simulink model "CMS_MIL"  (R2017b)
settings: Solver=FixedStepDiscrete  StartTime=0.0  StopTime=10.0  FixedStep=0.01  RelTol=1e-3  EnableMultiTasking=on
undefined symbols (not defined in the file): ASWTYPE_FALSE, ASWTYPE_TRUE, CcCMS_CANSendDelay_ms, CcCMS_ChrgMaxPackVoltLimt_V, CcCMS_ChrgRemTimeDftValDelayTime_ms, CcCMS_GBChgModeStayInCloseStatus_ms, CcCMS_PeakVoltCh_V, CcCMS_PeakVoltDisCh_V, CcSOC_DispSOCHighThrhd_pct, CMS09D_RUNTIME_MS, CMS_CONST0_NUMB, CMS_CONST1000_NUMB, CMS_CONST100_NUMB, CMS_CONST1_NUMB, CMS_CONST2047_NUMB, CMS_CONST2_NUMB, CMS_CONST3_NUMB, CMS_CONST4_NUMB, CMS_CONST5_NUMB, CMS_CONST6_NUMB, CMS_CONST7_NUMB, CMS_CONSTF1_NUMB, Enum_ACCACChrgState, Enum_CMSACChgMode, Enum_CMSBmsSelfChk, Enum_CMSBmsSt, Enum_CMSChgMode, Enum_CMSDCChgMode, Enum_CMSHVBatFltSevrtyStat, Enum_CMSHVConnSt, Enum_CMSPreThmMode, Enum_CMSPreThmReq, Enum_CTCCtrCtlConnMode, Enum_CTCCtrCtlState, Enum_DCCDCChrgState, Enum_DCCDCConnSt, Enum_ISOHVIsoFltLevel, Enum_LDPChrgGunState, Enum_MSMBMUState, Enum_ODPCCState, Enum_UDSAreaSel, Enum_VDPPreThmEna
libraries: AIWAYS_Powertrain_BMS_lib x156
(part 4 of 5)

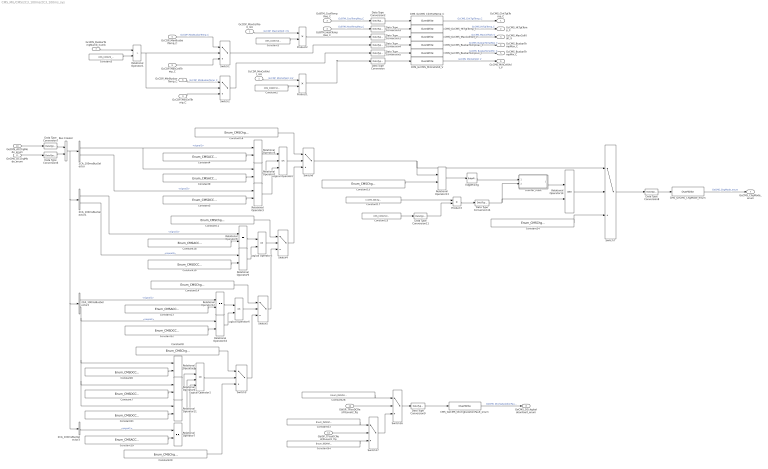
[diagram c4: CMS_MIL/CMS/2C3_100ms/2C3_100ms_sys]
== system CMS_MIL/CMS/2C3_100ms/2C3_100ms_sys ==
  GcCDP_MinCellVolt_mV : Inport
  GcCDP_MaxCellVolt_mV : Inport  Port=2
  GcBTM_CoolTempReq_C : Inport  Port=3
  GcBTM_HeatTempReq_C : Inport  Port=4
  GcCDP_MaxBusbarTemp_C : Inport  Port=5
  GcCDP_MinBusbarTemp_C : Inport  Port=6
  GcUDS_BusbarTempNumb_numb : Inport  Port=7
  GcCDP_MaxCellTemp_C : Inport  Port=8
  GcCDP_MinCellTemp_C : Inport  Port=9
  GeCMS_ACChgMode_enum : Inport  Port=10
  GeCMS_DCChgMode_enum : Inport  Port=11
  GbISP_TFIsoDCResFltLevel2_flg : Inport  Port=12
  GbISP_TFIsoDCResFltLevel1_flg : Inport  Port=13
  2CA_100msBusSelector : BusSelector  OutputSignals=signal1,signal2
  2CA_100msBusSelector1 : BusSelector  OutputSignals=signal1,signal2
  2CA_100msBusSelector2 : BusSelector  OutputSignals=signal1,signal2
  2CA_100msBusSelector3 : BusSelector  OutputSignals=signal1
  Bus Creator : BusCreator  Inputs=2
  CMS_GcCMS_BusbarTempMax_C : AIWAYS_Powertrain_BMS_lib/Signals/OverWrite  OverWrite_Value=CcCMS_BusbarTempMaxOvr_C  OverWrite_flag=CbCMS_BusbarTempMaxOvrSwt_flg
  CMS_GcCMS_BusbarTempMin_C : AIWAYS_Powertrain_BMS_lib/Signals/OverWrite  OverWrite_Value=CcCMS_BusbarTempMinOvr_C  OverWrite_flag=CbCMS_BusbarTempMinOvrSwt_flg
  CMS_GcCMS_ClntTgtTemp_C : AIWAYS_Powertrain_BMS_lib/Signals/OverWrite  OverWrite_Value=CcCMS_ClntTgtTempOvr_C  OverWrite_flag=CbCMS_ClntTgtTempOvrSwt_flg
  CMS_GcCMS_HtTgtTemp_C : AIWAYS_Powertrain_BMS_lib/Signals/OverWrite  OverWrite_Value=CcCMS_HtTgtTempOvr_C  OverWrite_flag=CbCMS_HtTgtTempOvrSwt_flg
  CMS_GcCMS_MaxCellVolt_V : AIWAYS_Powertrain_BMS_lib/Signals/OverWrite  OverWrite_Value=CcCMS_MaxCellVoltOvr_V  OverWrite_flag=CbCMS_MaxCellVoltOvrSwt_flg
  CMS_GcCMS_MinCellVolt_V : AIWAYS_Powertrain_BMS_lib/Signals/OverWrite  OverWrite_Value=CcCMS_MinCellVoltOvr_V  OverWrite_flag=CbCMS_MinCellVoltOvrSwt_flg
  CMS_GeCMS_ChgMode_enum : AIWAYS_Powertrain_BMS_lib/Signals/OverWrite  OverWrite_Value=CeCMS_ChgModeOvr_enum  OverWrite_flag=CbCMS_ChgModeOvrSwt_flg
  CMS_GeCMS_DCchgIsolationFault_enum : AIWAYS_Powertrain_BMS_lib/Signals/OverWrite  OverWrite_Value=CeCMS_DCchgIsolationFaultOvr_enum  OverWrite_flag=CbCMS_DCchgIsolationFaultOvrSwt_flg
  Constant1 : Constant  Value=CMS_CONST1000_NUMB
  Constant10 : Constant  Value=Enum_CMSDCChgMode.Enum_CMSDCChgMode_ChgEnd
  Constant11 : Constant  Value=Enum_CMSChgMode.Enum_CMSChgMode_Closed
  Constant12 : Constant  Value=Enum_CMSDCChgMode.Enum_CMSDCChgMode_ChgFault
  Constant13 : Constant  Value=Enum_CMSACChgMode.Enum_CMSACChgMode_ChrgFault
  Constant14 : Constant  Value=Enum_CMSChgMode.Enum_CMSChgMode_Abnormal
  Constant15 : Constant  Value=Enum_CMSChgMode.Enum_CMSChgMode_Closed
  Constant16 : Constant  Value=Enum_CMSChgMode.Enum_CMSChgMode_ParkingCharging
  Constant17 : Constant  Value=CcCMS_GBChgModeStayInCloseStatus_ms
  Constant18 : Constant  Value=Enum_CMSACChgMode.Enum_CMSACChgMode_ChrgEnd
  Constant19 : Constant  Value=Enum_CMSACChgMode.Enum_CMSACChgMode_Default
  Constant2 : Constant  Value=CMS_CONST1000_NUMB
  Constant20 : Constant  Value=Enum_CMSChgMode.Enum_CMSChgMode_Invalid
  Constant21 : Constant  Value=Enum_CMSDCChgMode.Enum_CMSDCChgMode_Default
  Constant23 : Constant  Value=CMS_CONST100_NUMB
  Constant24 : Constant  Value=Enum_CMSChgMode.Enum_CMSChgMode_Closed
  Constant28 : Constant  Value=Enum_ISOHVIsoFltLevel.Enum_ISOHVIsoFltLevel_FltLevel3
  Constant3 : Constant  Value=CMS_CONST0_NUMB
  Constant4 : Constant  Value=Enum_CMSACChgMode.Enum_CMSACChgMode_PreHeat
  Constant5 : Constant  Value=Enum_CMSDCChgMode.Enum_CMSDCChgMode_Chging
  Constant53 : Constant  Value=Enum_ISOHVIsoFltLevel.Enum_ISOHVIsoFltLevel_FltLevel2
  Constant54 : Constant  Value=Enum_ISOHVIsoFltLevel.Enum_ISOHVIsoFltLevel_Default
  Constant6 : Constant  Value=Enum_CMSDCChgMode.Enum_CMSDCChgMode_HandOver
  Constant7 : Constant  Value=Enum_CMSDCChgMode.Enum_CMSDCChgMode_ParaConfig
  Constant8 : Constant  Value=Enum_CMSChgMode.Enum_CMSChgMode_Uncharged
  Constant9 : Constant  Value=Enum_CMSACChgMode.Enum_CMSACChgMode_Chrging
  Data Type Conversion{,1,4..5} (4 alike) : DataTypeConversion  RndMeth=Round
  Data Type Conversion{2..3,6..9,11} (7 alike) : DataTypeConversion
  Data Type Conversion14 : DataTypeConversion  OutDataTypeStr=uint16
  EdgeRising : AIWAYS_Powertrain_BMS_lib/Logical Operators/EdgeRising
  Logical Operator1 : Logic  Operator=OR  Inputs=4  AllPortsSameDT=off  OutDataTypeStr=boolean
  Logical Operator2 : Logic  Operator=OR  Inputs=3  AllPortsSameDT=off  OutDataTypeStr=boolean
  Logical Operator3 : Logic  Operator=OR  AllPortsSameDT=off  OutDataTypeStr=boolean
  Logical Operator4 : Logic  Operator=OR  AllPortsSameDT=off  OutDataTypeStr=boolean
  Product1 : Product  Inputs=*/  OutDataTypeStr=single
  Product2 : Product  Inputs=*/  OutDataTypeStr=single
  Product3 : Product  Inputs=*/  OutDataTypeStr=Inherit: Inherit via back propagation
  Relational Operator1 : RelationalOperator  Operator=>  OutDataTypeStr=boolean
  Relational Operator{2..13} (12 alike) : RelationalOperator  Operator===  OutDataTypeStr=boolean
  Relational Operator14 : RelationalOperator  OutDataTypeStr=boolean
  Switch1 : Switch  Criteria=u2 ~= 0  Threshold=1  RndMeth=Zero
  Switch{3..7,16..17} (7 alike) : Switch  Criteria=u2 ~= 0
  Switch2 : Switch  Criteria=u2 ~= 0  Threshold=1  RndMeth=Zero
  counter_reset : Subsystem
  GcCMS_ClntTgtTemp_C : Outport
  GcCMS_HtTgtTemp_C : Outport  Port=2
  GcCMS_MaxCellVolt_V : Outport  Port=3
  GcCMS_BusbarTempMax_C : Outport  Port=4
  GcCMS_BusbarTempMin_C : Outport  Port=5
  GcCMS_MinCellVolt_V : Outport  Port=6
  GeCMS_ChgMode_enum : Outport  Port=7
  GeCMS_DCchgIsolationFault_enum : Outport  Port=8
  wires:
  CMS_GcCMS_ClntTgtTemp_C/1 -> GcCMS_ClntTgtTemp_C/1  "GcCMS_ClntTgtTemp_C"
  CMS_GcCMS_BusbarTempMin_C/1 -> GcCMS_BusbarTempMin_C/1  "GcCMS_BusbarTempMin_C"
  CMS_GcCMS_BusbarTempMax_C/1 -> GcCMS_BusbarTempMax_C/1  "GcCMS_BusbarTempMax_C"
  CMS_GcCMS_MaxCellVolt_V/1 -> GcCMS_MaxCellVolt_V/1  "GcCMS_MaxCellVolt_V"
  CMS_GcCMS_HtTgtTemp_C/1 -> GcCMS_HtTgtTemp_C/1  "GcCMS_HtTgtTemp_C"
  Constant2/1 -> Product1/2
  GcCDP_MinCellVolt_mV/1 -> Product1/1  "GcCDP_MinCellVolt_mV"
  CMS_GcCMS_MinCellVolt_V/1 -> GcCMS_MinCellVolt_V/1  "GcCMS_MinCellVolt_V"
  Product1/1 -> Data Type Conversion/1
  GcBTM_CoolTempReq_C/1 -> Data Type Conversion2/1  "GcBTM_CoolTempReq_C"
  GcBTM_HeatTempReq_C/1 -> Data Type Conversion3/1  "GcBTM_HeatTempReq_C"
  GcCDP_MaxBusbarTemp_C/1 -> Switch1/1  "GcCDP_MaxBusbarTemp_C"
  GcCDP_MinBusbarTemp_C/1 -> Switch2/1  "GcCDP_MinBusbarTemp_C"
  Data Type Conversion/1 -> CMS_GcCMS_MinCellVolt_V/1
  GcCDP_MaxCellVolt_mV/1 -> Product2/1  "GcCDP_MaxCellVolt_mV"
  Product2/1 -> Data Type Conversion1/1
  Constant1/1 -> Product2/2
  Data Type Conversion1/1 -> CMS_GcCMS_MaxCellVolt_V/1
  Data Type Conversion2/1 -> CMS_GcCMS_ClntTgtTemp_C/1
  Data Type Conversion3/1 -> CMS_GcCMS_HtTgtTemp_C/1
  Data Type Conversion4/1 -> CMS_GcCMS_BusbarTempMax_C/1
  Data Type Conversion5/1 -> CMS_GcCMS_BusbarTempMin_C/1
  GcUDS_BusbarTempNumb_numb/1 -> Relational Operator1/1
  Constant3/1 -> Relational Operator1/2
  Relational Operator1/1 -> Switch2/2, Switch1/2
  GcCDP_MaxCellTemp_C/1 -> Switch1/3
  Switch1/1 -> Data Type Conversion4/1
  GcCDP_MinCellTemp_C/1 -> Switch2/3
  Switch2/1 -> Data Type Conversion5/1
  Switch3/1 -> Switch5/3
  Relational Operator7/1 -> Logical Operator1/4
  Relational Operator10/1 -> Logical Operator4/2
  Logical Operator3/1 -> Switch4/2
  GeCMS_ACChgMode_enum/1 -> Data Type Conversion7/1
  Constant16/1 -> Switch6/1
  Data Type Conversion8/1 -> CMS_GeCMS_ChgMode_enum/1
  Constant4/1 -> Relational Operator5/2
  Constant9/1 -> Relational Operator2/2
  Constant21/1 -> Relational Operator11/2
  Constant18/1 -> Relational Operator8/2
  2CA_100msBusSelector2/1 -> Relational Operator12/1  "<signal1>"
  Relational Operator3/1 -> Logical Operator2/3
  Constant10/1 -> Relational Operator9/2
  Relational Operator2/1 -> Logical Operator2/2
  Constant20/1 -> Switch3/3
  2CA_100msBusSelector/1 -> Relational Operator5/1, Relational Operator2/1  "<signal1>"
  Logical Operator1/1 -> Switch3/2
  Constant5/1 -> Relational Operator3/2
  Constant8/1 -> Switch3/1
  Relational Operator11/1 -> Logical Operator1/3
  Constant14/1 -> Switch5/1
  Constant6/1 -> Relational Operator4/2
  Switch4/1 -> Switch6/3
  2CA_100msBusSelector1/1 -> Relational Operator8/1  "<signal1>"
  Constant13/1 -> Relational Operator12/2
  Switch5/1 -> Switch4/3
  Relational Operator6/1 -> Logical Operator1/2
  Constant12/1 -> Relational Operator10/2
  Logical Operator2/1 -> Switch6/2
  2CA_100msBusSelector3/1 -> Relational Operator7/1  "<signal1>"
  Relational Operator9/1 -> Logical Operator3/2
  Data Type Conversion7/1 -> Bus Creator/1
  2CA_100msBusSelector/2 -> Relational Operator3/1  "<signal2>"
  Constant7/1 -> Relational Operator6/2
  2CA_100msBusSelector1/2 -> Relational Operator9/1  "<signal2>"
  GeCMS_DCChgMode_enum/1 -> Data Type Conversion6/1
  Bus Creator/1 -> 2CA_100msBusSelector/1, 2CA_100msBusSelector1/1, 2CA_100msBusSelector2/1, 2CA_100msBusSelector3/1
  Relational Operator12/1 -> Logical Operator4/1
  2CA_100msBusSelector2/2 -> Relational Operator10/1, Relational Operator6/1, Relational Operator11/1, Relational Operator4/1  "<signal2>"
  Data Type Conversion6/1 -> Bus Creator/2
  Relational Operator8/1 -> Logical Operator3/1
  Relational Operator5/1 -> Logical Operator2/1
  CMS_GeCMS_ChgMode_enum/1 -> GeCMS_ChgMode_enum/1  "GeCMS_ChgMode_enum"
  Logical Operator4/1 -> Switch5/2
  Switch6/1 -> Relational Operator13/1, Switch7/1
  Constant19/1 -> Relational Operator7/2
  Relational Operator4/1 -> Logical Operator1/1
  Constant11/1 -> Switch4/1
  Switch17/1 -> Switch16/3
  Constant54/1 -> Switch17/3
  GbISP_TFIsoDCResFltLevel2_flg/1 -> Switch16/2
  GbISP_TFIsoDCResFltLevel1_flg/1 -> Switch17/2
  Constant28/1 -> Switch16/1
  Constant53/1 -> Switch17/1
  Switch16/1 -> Data Type Conversion9/1
  CMS_GeCMS_DCchgIsolationFault_enum/1 -> GeCMS_DCchgIsolationFault_enum/1  "GeCMS_DCchgIsolationFault_enum"
  Data Type Conversion9/1 -> CMS_GeCMS_DCchgIsolationFault_enum/1
  Constant15/1 -> Relational Operator13/2
  Relational Operator13/1 -> EdgeRising/1
  Relational Operator14/1 -> Switch7/2
  Switch7/1 -> Data Type Conversion8/1
  Constant23/1 -> Data Type Conversion11/1
  Data Type Conversion11/1 -> Product3/2
  counter_reset/1(cnt_num) -> Relational Operator14/1
  Data Type Conversion14/1 -> Relational Operator14/2, counter_reset/2(max_cnt)
  Constant24/1 -> Switch7/3
  EdgeRising/1 -> counter_reset/1(reset)
  Product3/1 -> Data Type Conversion14/1
  Constant17/1 -> Product3/1

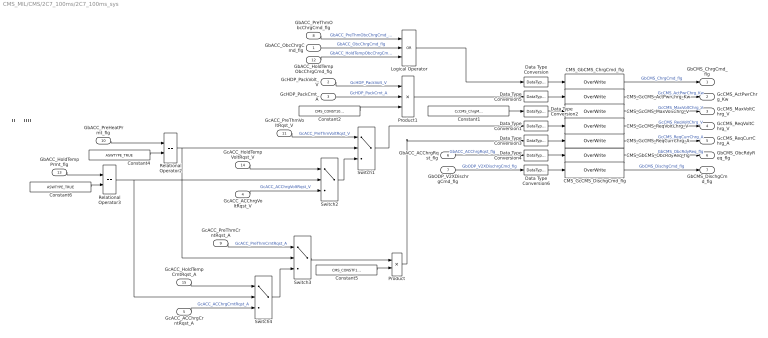
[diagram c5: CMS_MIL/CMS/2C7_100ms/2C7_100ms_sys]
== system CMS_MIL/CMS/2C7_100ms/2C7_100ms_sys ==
  note: 预加热 保温 充电
  GbACC_ObcChrgCmd_flg : Inport
  GcHDP_PackVolt_V : Inport  Port=2
  GcHDP_PackCrnt_A : Inport  Port=3
  GcACC_ACChrgVoltRqst_V : Inport  Port=4
  GcACC_ACChrgCrntRqst_A : Inport  Port=5
  GbACC_ACChrgRqst_flg : Inport  Port=6
  GbODP_V2XDischrgCmd_flg : Inport  Port=7
  GbACC_PreThmObcChrgCmd_flg : Inport  Port=8
  GcACC_PreThmCrntRqst_A : Inport  Port=9
  GbACC_PreHeatPrmt_flg : Inport  Port=10
  GcACC_PreThmVoltRqst_V : Inport  Port=11
  GbACC_HoldTempObcChrgCmd_flg : Inport  Port=12
  GbACC_HoldTempPrmt_flg : Inport  Port=13
  GcACC_HoldTempVoltRqst_V : Inport  Port=14
  GcACC_HoldTempCrntRqst_A : Inport  Port=15
  CMS_GbCMS_ChrgCmd_flg : AIWAYS_Powertrain_BMS_lib/Signals/OverWrite  OverWrite_Value=CbCMS_ChrgCmdOvr_flg  OverWrite_flag=CbCMS_ChrgCmdOvrSwt_flg
  CMS_GbCMS_ObcRdyReq_flg : AIWAYS_Powertrain_BMS_lib/Signals/OverWrite  OverWrite_Value=CbCMS_ObcRdyReqOvr_flg  OverWrite_flag=CbCMS_ObcRdyReqOvrSwt_flg
  CMS_GcCMS_ActPwrChrg_Kw : AIWAYS_Powertrain_BMS_lib/Signals/OverWrite  OverWrite_Value=CcCMS_ActPwrChrgOvr_Kw  OverWrite_flag=CbCMS_ActPwrChrgOvrSwt_flg
  CMS_GcCMS_DischgCmd_flg : AIWAYS_Powertrain_BMS_lib/Signals/OverWrite  OverWrite_Value=CbCMS_DischgCmdOvr_flg  OverWrite_flag=CbCMS_DischgCmdOvrSwt_flg
  CMS_GcCMS_MaxVoltChrg_V : AIWAYS_Powertrain_BMS_lib/Signals/OverWrite  OverWrite_Value=CcCMS_MaxVoltChrgOvr_V  OverWrite_flag=CbCMS_MaxVoltChrgOvrSwt_flg
  CMS_GcCMS_ReqCurrChrg_A : AIWAYS_Powertrain_BMS_lib/Signals/OverWrite  OverWrite_Value=CcCMS_ReqCurrChrgOvr_A  OverWrite_flag=CbCMS_ReqCurrChrgOvrSwt_flg
  CMS_GcCMS_ReqVoltChrg_V : AIWAYS_Powertrain_BMS_lib/Signals/OverWrite  OverWrite_Value=CcCMS_ReqVoltChrgOvr_V  OverWrite_flag=CbCMS_ReqVoltChrgOvrSwt_flg
  Constant1 : Constant  Value=CcCMS_ChrgMaxPackVoltLimt_V
  Constant2 : Constant  Value=CMS_CONST1000_NUMB
  Constant4 : Constant  Value=ASWTYPE_TRUE
  Constant5 : Constant  Value=CMS_CONSTF1_NUMB
  Constant6 : Constant  Value=ASWTYPE_TRUE
  Data Type Conversion{,1..6} (7 alike) : DataTypeConversion
  Logical Operator : Logic  Operator=OR  Inputs=3  AllPortsSameDT=off  OutDataTypeStr=boolean
  Product : Product  OutDataTypeStr=Inherit: Inherit via back propagation
  Product1 : Product  Inputs=**/  OutDataTypeStr=single
  Relational Operator2 : RelationalOperator  Operator===  OutDataTypeStr=boolean
  Relational Operator3 : RelationalOperator  Operator===  OutDataTypeStr=boolean
  Switch{1..4} (4 alike) : Switch  Criteria=u2 ~= 0  Threshold=1  RndMeth=Zero
  GbCMS_ChrgCmd_flg : Outport
  GcCMS_ActPwrChrg_Kw : Outport  Port=2
  GcCMS_MaxVoltChrg_V : Outport  Port=3
  GcCMS_ReqVoltChrg_V : Outport  Port=4
  GcCMS_ReqCurrChrg_A : Outport  Port=5
  GbCMS_ObcRdyReq_flg : Outport  Port=6
  GbCMS_DischgCmd_flg : Outport  Port=7
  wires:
  CMS_GbCMS_ChrgCmd_flg/1 -> GbCMS_ChrgCmd_flg/1  "GbCMS_ChrgCmd_flg"
  CMS_GcCMS_ActPwrChrg_Kw/1 -> GcCMS_ActPwrChrg_Kw/1  "GcCMS_ActPwrChrg_Kw"
  CMS_GcCMS_MaxVoltChrg_V/1 -> GcCMS_MaxVoltChrg_V/1  "GcCMS_MaxVoltChrg_V"
  CMS_GcCMS_ReqVoltChrg_V/1 -> GcCMS_ReqVoltChrg_V/1  "GcCMS_ReqVoltChrg_V"
  CMS_GcCMS_ReqCurrChrg_A/1 -> GcCMS_ReqCurrChrg_A/1  "GcCMS_ReqCurrChrg_A"
  CMS_GbCMS_ObcRdyReq_flg/1 -> GbCMS_ObcRdyReq_flg/1  "GbCMS_ObcRdyReq_flg"
  CMS_GcCMS_DischgCmd_flg/1 -> GbCMS_DischgCmd_flg/1  "GbCMS_DischgCmd_flg"
  GbACC_ObcChrgCmd_flg/1 -> Logical Operator/2  "GbACC_ObcChrgCmd_flg"
  Data Type Conversion/1 -> CMS_GbCMS_ChrgCmd_flg/1
  GcHDP_PackVolt_V/1 -> Product1/1  "GcHDP_PackVolt_V"
  GcHDP_PackCrnt_A/1 -> Product1/2  "GcHDP_PackCrnt_A"
  Product1/1 -> Data Type Conversion5/1
  Constant2/1 -> Product1/3
  GcACC_ACChrgVoltRqst_V/1 -> Switch2/3  "GcACC_ACChrgVoltRqst_V"
  GcACC_ACChrgCrntRqst_A/1 -> Switch4/3  "GcACC_ACChrgCrntRqst_A"
  GbACC_ACChrgRqst_flg/1 -> Data Type Conversion4/1  "GbACC_ACChrgRqst_flg"
  Data Type Conversion6/1 -> CMS_GcCMS_DischgCmd_flg/1
  Data Type Conversion1/1 -> CMS_GcCMS_ReqVoltChrg_V/1
  Data Type Conversion2/1 -> CMS_GcCMS_MaxVoltChrg_V/1
  Data Type Conversion3/1 -> CMS_GcCMS_ReqCurrChrg_A/1
  Data Type Conversion4/1 -> CMS_GbCMS_ObcRdyReq_flg/1
  Data Type Conversion5/1 -> CMS_GcCMS_ActPwrChrg_Kw/1
  GbODP_V2XDischrgCmd_flg/1 -> Data Type Conversion6/1  "GbODP_V2XDischrgCmd_flg"
  Constant1/1 -> Data Type Conversion2/1
  GbACC_PreThmObcChrgCmd_flg/1 -> Logical Operator/1  "GbACC_PreThmObcChrgCmd_flg"
  Logical Operator/1 -> Data Type Conversion/1
  Relational Operator2/1 -> Switch1/2, Switch3/2
  GcACC_PreThmCrntRqst_A/1 -> Switch3/1  "GcACC_PreThmCrntRqst_A"
  Switch3/1 -> Product/1
  GbACC_PreHeatPrmt_flg/1 -> Relational Operator2/1
  Constant4/1 -> Relational Operator2/2
  GcACC_PreThmVoltRqst_V/1 -> Switch1/1  "GcACC_PreThmVoltRqst_V"
  Switch1/1 -> Data Type Conversion1/1
  Constant5/1 -> Product/2
  Product/1 -> Data Type Conversion3/1
  GbACC_HoldTempObcChrgCmd_flg/1 -> Logical Operator/3  "GbACC_HoldTempObcChrgCmd_flg"
  Constant6/1 -> Relational Operator3/2
  GbACC_HoldTempPrmt_flg/1 -> Relational Operator3/1
  Relational Operator3/1 -> Switch4/2, Switch2/2
  Switch2/1 -> Switch1/3
  GcACC_HoldTempVoltRqst_V/1 -> Switch2/1
  Switch4/1 -> Switch3/3
  GcACC_HoldTempCrntRqst_A/1 -> Switch4/1

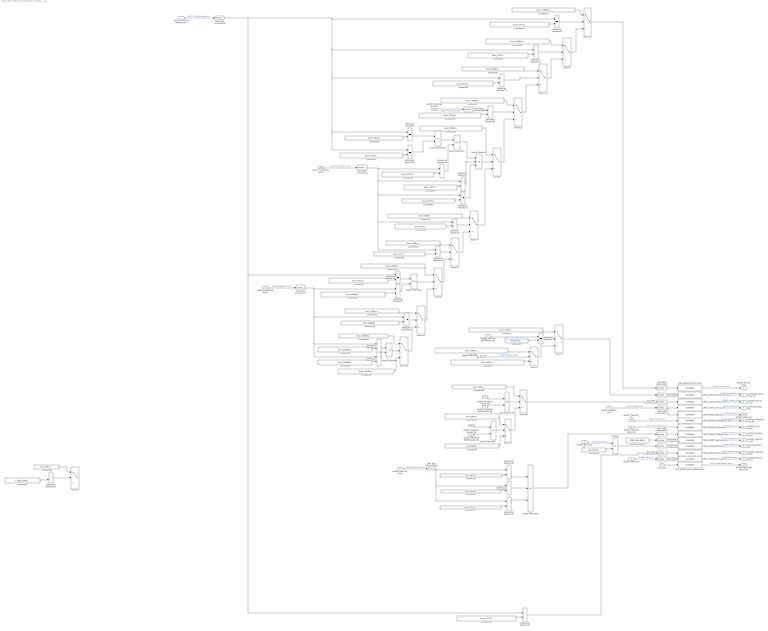
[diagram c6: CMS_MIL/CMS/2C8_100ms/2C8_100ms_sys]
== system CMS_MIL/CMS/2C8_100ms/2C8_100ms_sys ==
  GeCTC_CtrCtlConnMode_enum : Inport
  GbMSM_SelfCheck_flg : Inport  Port=2
  GcSOC_DispSOC_pct : Inport  Port=3
  GbISP_TFHvilLFlt_flg : Inport  Port=4
  GeFTC_FltLvlOnCAN_enum : Inport  Port=5
  GcSOH_PackSOH_pct : Inport  Port=6
  GcHDP_HallCrnt_A : Inport  Port=7
  GbMSM_SelfChckMaxTiReach_flg : Inport  Port=8
  GeMSM_BMUState_enum : Inport  Port=9
  GeCTC_CtrCtlState_enum : Inport  Port=10
  GeODP_ObcCcSt_enum : Inport  Port=11
  GeVDP_PreThmEna_enum : Inport  Port=12
  GbISP_TFIsoResFltLevel2_flg : Inport  Port=13
  GbISP_TFIsoHVoffResFltLevel2_flg : Inport  Port=14
  GbISP_TFIsoResFltLevel1_flg : Inport  Port=15
  GbISP_TFIsoHVoffResFltLevel1_flg : Inport  Port=16
  CMS_GbCMS_HvilOpenFault_flg : AIWAYS_Powertrain_BMS_lib/Signals/OverWrite  OverWrite_Value=CbCMS_HvilOpenFaultOvr_flg  OverWrite_flag=CbCMS_HvilOpenFaultOvrSwt_flg
  CMS_GcCMS_BattSoh_pct : AIWAYS_Powertrain_BMS_lib/Signals/OverWrite  OverWrite_Value=CcCMS_BattSohOvr_pct  OverWrite_flag=CbCMS_BattSohOvrSwt_flg
  CMS_GcCMS_ChgSOCset_pct : AIWAYS_Powertrain_BMS_lib/Signals/OverWrite  OverWrite_Value=CcCMS_ChgSOCsetOvr_pct  OverWrite_flag=CbCMS_ChgSOCsetOvrSwt_flg
  CMS_GcCMS_IsoFault_enum : AIWAYS_Powertrain_BMS_lib/Signals/OverWrite  OverWrite_Value=CeCMS_IsoFaultOvr_enum  OverWrite_flag=CbCMS_IsoFaultOvrSwt_flg
  CMS_GcCMS_PackCurLem_A : AIWAYS_Powertrain_BMS_lib/Signals/OverWrite  OverWrite_Value=CcCMS_PackCurLemOvr_A  OverWrite_flag=CbCMS_PackCurLemOvrSwt_flg
  CMS_GcCMS_SOCA_pct : AIWAYS_Powertrain_BMS_lib/Signals/OverWrite  OverWrite_Value=CcCMS_SOCAOvr_pct  OverWrite_flag=CbCMS_SOCAOvrSwt_flg
  CMS_GcCMS_SocDspl_pct : AIWAYS_Powertrain_BMS_lib/Signals/OverWrite  OverWrite_Value=CcCMS_SocDsplOvr_pct  OverWrite_flag=CbCMS_SocDsplOvrSwt_flg
  CMS_GeCMS_AppChgMode_enum : AIWAYS_Powertrain_BMS_lib/Signals/OverWrite  OverWrite_Value=CeCMS_AppChgModeOvr_enum  OverWrite_flag=CbCMS_AppChgModeOvrSwt_flg
  CMS_GeCMS_BmsSelfChk_enum : AIWAYS_Powertrain_BMS_lib/Signals/OverWrite  OverWrite_Value=CeCMS_BmsSelfChkOvr_enum  OverWrite_flag=CbCMS_BmsSelfChkOvrSwt_flg
  CMS_GeCMS_BmsSt_enum : AIWAYS_Powertrain_BMS_lib/Signals/OverWrite  OverWrite_Value=CeCMS_BmsStOvr_enum  OverWrite_flag=CbCMS_BmsStOvrSwt_flg
  CMS_GeCMS_FltLvl_enum : AIWAYS_Powertrain_BMS_lib/Signals/OverWrite  OverWrite_Value=CeCMS_FltLvlOvr_enum  OverWrite_flag=CbCMS_FltLvlOvrSwt_flg
  CMS_GeCMS_IviDischg_enum : AIWAYS_Powertrain_BMS_lib/Signals/OverWrite  OverWrite_Value=CeCMS_IviDischgOvr_enum  OverWrite_flag=CbCMS_IviDischgOvrSwt_flg
  CMS_GeCMS_V2xMod_enum : AIWAYS_Powertrain_BMS_lib/Signals/OverWrite  OverWrite_Value=CeCMS_V2xModOvr_enum  OverWrite_flag=CbCMS_V2xModOvrSwt_flg
  Constant14 : Constant  Value=Enum_MSMBMUState.Enum_MSMBMUState_Run
  Constant15 : Constant  Value=Enum_CMSBmsSt.Enum_CMSBmsSt_Standby
  Constant16 : Constant  Value=Enum_CTCCtrCtlState.Enum_CTCCtrCtlState_Connect
  Constant17 : Constant  Value=Enum_CTCCtrCtlState.Enum_CTCCtrCtlState_DCConnect
  Constant18 : Constant  Value=Enum_CMSBmsSt.Enum_CMSBmsSt_Prechrge
  Constant19 : Constant  Value=Enum_ODPCCState.Enum_ODPCCState_DisChrgConnect32A1000
  Constant20 : Constant  Value=Enum_CTCCtrCtlConnMode.Enum_CTCCtrCtlConnMode_Drive
  Constant21 : Constant  Value=Enum_CMSBmsSt.Enum_CMSBmsSt_HVON
  Constant22 : Constant  Value=Enum_MSMBMUState.Enum_MSMBMUState_Shutdown
  Constant23 : Constant  Value=Enum_CTCCtrCtlConnMode.Enum_CTCCtrCtlConnMode_ACChrg
  Constant24 : Constant  Value=Enum_CMSBmsSt.Enum_CMSBmsSt_ACChrge
  Constant25 : Constant  Value=Enum_CMSBmsSt.Enum_CMSBmsSt_AfterRun
  Constant26 : Constant  Value=Enum_CTCCtrCtlConnMode.Enum_CTCCtrCtlConnMode_DCChrg
  Constant27 : Constant  Value=Enum_CMSBmsSt.Enum_CMSBmsSt_DCChrge
  Constant28 : Constant  Value=Enum_ISOHVIsoFltLevel.Enum_ISOHVIsoFltLevel_FltLevel3
  Constant29 : Constant  Value=Enum_CMSBmsSt.Enum_CMSBmsSt_V2X
  Constant30 : Constant  Value=Enum_CTCCtrCtlConnMode.Enum_CTCCtrCtlConnMode_VTX
  Constant31 : Constant  Value=Enum_CTCCtrCtlConnMode.Enum_CTCCtrCtlConnMode_Default
  Constant32 : Constant  Value=Enum_ODPCCState.Enum_ODPCCState_DisChrgConnect10A2700
  Constant33 : Constant  Value=Enum_ODPCCState.Enum_ODPCCState_DisChrgConnect16A2000
  Constant34 : Constant  Value=CMS_CONST100_NUMB
  Constant35 : Constant  Value=Enum_CTCCtrCtlConnMode.Enum_CTCCtrCtlConnMode_VTX
  Constant36 : Constant  Value=Enum_CTCCtrCtlState.Enum_CTCCtrCtlState_Online
  Constant37 : Constant  Value=Enum_CMSBmsSt.Enum_CMSBmsSt_PreHeat
  Constant38 : Constant  Value=Enum_MSMBMUState.Enum_MSMBMUState_Standby
  Constant39 : Constant  Value=Enum_CMSBmsSt.Enum_CMSBmsSt_Default
  Constant40 : Constant  Value=Enum_VDPPreThmEna.Enum_VDPPreThmEna_PreHeatEna
  Constant41 : Constant  Value=Enum_CMSBmsSt.Enum_CMSBmsSt_Init
  Constant47 : Constant  Commented=on  Value=CcSOC_DispSOCHighThrhd_pct
  Constant48 : Constant  Commented=on  Value=CMS_CONST100_NUMB
  Constant49 : Constant  Value=Enum_CTCCtrCtlState.Enum_CTCCtrCtlState_Shutdown
  Constant50 : Constant  Value=Enum_CMSBmsSt.Enum_CMSBmsSt_HVoff
  Constant51 : Constant  Value=Enum_CTCCtrCtlState.Enum_CTCCtrCtlState_PreShutdown
  Constant53 : Constant  Value=Enum_ISOHVIsoFltLevel.Enum_ISOHVIsoFltLevel_FltLevel2
  Constant54 : Constant  Value=Enum_ISOHVIsoFltLevel.Enum_ISOHVIsoFltLevel_Default
  Constant55 : Constant  Value=Enum_MSMBMUState.Enum_MSMBMUState_PreShutdown
  Constant57 : Constant  Value=Enum_CTCCtrCtlConnMode.Enum_CTCCtrCtlConnMode_SelfDischrg
  Constant6 : Constant  Value=Enum_CMSBmsSelfChk.Enum_CMSBmsSelfChk_NoFault
  Constant7 : Constant  Value=Enum_CMSBmsSelfChk.Enum_CMSBmsSelfChk_SelfChecking
  Constant8 : Constant  Value=ASWTYPE_FALSE
  Constant9 : Constant  Value=Enum_CMSBmsSelfChk.Enum_CMSBmsSelfChk_Fault
  Data Store Read1 : AIWAYS_Powertrain_BMS_lib/Signals/Data Store Read  Priority=0  DSR=EcNVM_ChrgPermitMaxSOC_pct
  Data Type Conversion{1,3..4,6..12,14..15} (12 alike) : DataTypeConversion
  Data Type Conversion13 : DataTypeConversion  RndMeth=Round
  Data Type Conversion5 : DataTypeConversion  RndMeth=Round
  Ground12 : Ground
  Logical Operator1 : Logic  Operator=OR  Inputs=3  AllPortsSameDT=off  OutDataTypeStr=boolean
  Logical Operator2 : Logic  Operator=OR  Inputs=3  AllPortsSameDT=off  OutDataTypeStr=boolean
  Logical Operator3 : Logic  AllPortsSameDT=off  OutDataTypeStr=boolean
  Logical Operator4 : Logic  AllPortsSameDT=off  OutDataTypeStr=boolean
  Logical Operator{5,7..9} (4 alike) : Logic  Operator=OR  AllPortsSameDT=off  OutDataTypeStr=boolean
  Product : Product  OutDataTypeStr=Inherit: Inherit via back propagation
  Relational Operator{4..21,30..31,33} (21 alike) : RelationalOperator  Operator===  OutDataTypeStr=boolean
  Relational Operator29 : RelationalOperator  Commented=on  Operator=>  OutDataTypeStr=boolean
  Switch{4..17} (14 alike) : Switch  Criteria=u2 ~= 0
  Switch2 : Switch  Commented=on  Criteria=u2 ~= 0
  GeCMS_BmsSt_enum : Outport
  GeCMS_BmsSelfChk_enum : Outport  Port=2
  GeCMS_IsoFault_enum : Outport  Port=3
  GcCMS_SocDspl_pct : Outport  Port=4
  GbCMS_HvilOpenFault_flg : Outport  Port=5
  GeCMS_FltLvl_enum : Outport  Port=6
  GeCMS_V2xMod_enum : Outport  Port=7
  GcCMS_ChgSOCset_pct : Outport  Port=8
  GcCMS_BattSoh_pct : Outport  Port=9
  GcCMS_SOCA_pct : Outport  Port=10
  GeCMS_IviDischg_enum : Outport  Port=11
  GcCMS_PackCurLem_A : Outport  Port=12
  GeCMS_AppChgMode_enum : Outport  Port=13
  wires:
  CMS_GeCMS_BmsSt_enum/1 -> GeCMS_BmsSt_enum/1  "GeCMS_BmsSt_enum"
  CMS_GeCMS_BmsSelfChk_enum/1 -> GeCMS_BmsSelfChk_enum/1  "GeCMS_BmsSelfChk_enum"
  CMS_GcCMS_IsoFault_enum/1 -> GeCMS_IsoFault_enum/1  "GeCMS_IsoFault_enum"
  CMS_GcCMS_SocDspl_pct/1 -> GcCMS_SocDspl_pct/1  "GcCMS_SocDspl_pct"
  CMS_GbCMS_HvilOpenFault_flg/1 -> GbCMS_HvilOpenFault_flg/1  "GbCMS_HvilOpenFault_flg"
  CMS_GeCMS_FltLvl_enum/1 -> GeCMS_FltLvl_enum/1  "GeCMS_FltLvl_enum"
  CMS_GeCMS_V2xMod_enum/1 -> GeCMS_V2xMod_enum/1  "GeCMS_V2xMod_enum"
  CMS_GcCMS_BattSoh_pct/1 -> GcCMS_BattSoh_pct/1  "GcCMS_BattSoh_pct"
  CMS_GcCMS_SOCA_pct/1 -> GcCMS_SOCA_pct/1  "GcCMS_SOCA_pct"
  CMS_GeCMS_IviDischg_enum/1 -> GeCMS_IviDischg_enum/1  "GeCMS_IviDischg_enum"
  CMS_GcCMS_PackCurLem_A/1 -> GcCMS_PackCurLem_A/1  "GcCMS_PackCurLem_A"
  GcHDP_HallCrnt_A/1 -> Data Type Conversion3/1  "GcHDP_HallCrnt_A"
  GcSOH_PackSOH_pct/1 -> Product/1  "GcSOH_PackSOH_pct"
  GbISP_TFHvilLFlt_flg/1 -> CMS_GbCMS_HvilOpenFault_flg/1  "GbISP_TFHvilLFlt_flg"
  GcSOC_DispSOC_pct/1 -> Data Type Conversion13/1  "GcSOC_DispSOC_pct"
  GeCTC_CtrCtlConnMode_enum/1 -> Data Type Conversion6/1  "GeCTC_CtrCtlConnMode_enum"
  Data Store Read1/1 -> Data Type Conversion14/1
  Data Type Conversion12/1 -> CMS_GeCMS_IviDischg_enum/1
  GeFTC_FltLvlOnCAN_enum/1 -> CMS_GeCMS_FltLvl_enum/1  "GeFTC_FltLvlOnCAN_enum"
  GbMSM_SelfCheck_flg/1 -> Switch4/2  "GbMSM_SelfCheck_flg"
  Constant6/1 -> Switch4/1
  Switch4/1 -> Switch5/3
  Constant7/1 -> Switch5/1
  Constant8/1 -> Relational Operator4/2
  GbMSM_SelfChckMaxTiReach_flg/1 -> Relational Operator4/1  "GbMSM_SelfChckMaxTiReach_flg"
  Relational Operator4/1 -> Switch5/2
  Constant9/1 -> Switch4/3
  Switch5/1 -> Data Type Conversion1/1
  Data Type Conversion1/1 -> CMS_GeCMS_BmsSelfChk_enum/1
  Data Type Conversion3/1 -> CMS_GcCMS_PackCurLem_A/1
  Data Type Conversion13/1 -> CMS_GcCMS_SOCA_pct/1, CMS_GcCMS_SocDspl_pct/1
  Data Type Conversion5/1 -> CMS_GcCMS_BattSoh_pct/1
  GeMSM_BMUState_enum/1 -> Data Type Conversion7/1  "GeMSM_BMUState_enum"
  GeCTC_CtrCtlState_enum/1 -> Data Type Conversion8/1  "GeCTC_CtrCtlState_enum"
  Data Type Conversion7/1 -> Relational Operator5/1, Relational Operator19/1, Relational Operator14/1, Relational Operator10/1
  Constant14/1 -> Relational Operator5/2
  Relational Operator5/1 -> Logical Operator4/2
  Constant15/1 -> Switch6/1
  Constant16/1 -> Relational Operator6/2
  Constant17/1 -> Relational Operator7/2
  Relational Operator7/1 -> Logical Operator2/2
  Relational Operator6/1 -> Switch7/2
  Constant18/1 -> Switch7/1
  Switch7/1 -> Switch8/3
  Constant20/1 -> Relational Operator9/2
  Switch8/1 -> Switch13/3
  Constant21/1 -> Switch8/1
  Switch9/1 -> Switch10/3
  Constant23/1 -> Relational Operator11/2
  Data Type Conversion8/1 -> Relational Operator31/1, Relational Operator30/1, Relational Operator6/1, Relational Operator7/1, Relational Operator18/1
  Relational Operator11/1 -> Switch9/2
  Constant24/1 -> Switch9/1
  Constant27/1 -> Switch10/1
  Relational Operator13/1 -> Switch10/2
  Constant26/1 -> Relational Operator13/2
  Constant22/1 -> Relational Operator10/2
  Relational Operator10/1 -> Logical Operator8/1
  Switch11/1 -> Switch14/3
  Constant25/1 -> Switch11/1
  Switch12/1 -> Switch9/3
  Constant29/1 -> Switch12/1
  Relational Operator12/1 -> Switch12/2
  Constant30/1 -> Relational Operator12/2
  Switch10/1 -> Data Type Conversion9/1
  Data Type Conversion9/1 -> CMS_GeCMS_BmsSt_enum/1
  GeODP_ObcCcSt_enum/1 -> Data Type Conversion10/1  "GeODP_ObcCcSt_enum"
  Constant33/1 -> Relational Operator8/2
  Constant32/1 -> Relational Operator16/2
  Relational Operator15/1 -> Logical Operator1/3
  Relational Operator8/1 -> Logical Operator1/2
  Constant19/1 -> Relational Operator15/2
  Relational Operator16/1 -> Logical Operator1/1
  Data Type Conversion10/1 -> Relational Operator16/1, Relational Operator15/1, Relational Operator8/1
  Data Type Conversion11/1 -> CMS_GeCMS_V2xMod_enum/1
  Logical Operator1/1 -> Data Type Conversion11/1
  Constant34/1 -> Product/2
  Product/1 -> Data Type Conversion5/1
  Constant35/1 -> Relational Operator17/2
  Relational Operator17/1 -> Data Type Conversion12/1
  Relational Operator18/1 -> Logical Operator3/2
  Constant36/1 -> Relational Operator18/2
  Logical Operator3/1 -> Logical Operator2/1
  Constant39/1 -> Switch11/3
  Relational Operator21/1 -> Switch13/2
  Constant37/1 -> Switch13/1
  Switch13/1 -> Switch12/3
  GeVDP_PreThmEna_enum/1 -> Data Type Conversion4/1  "GeVDP_PreThmEna_enum"
  Data Type Conversion4/1 -> Relational Operator21/1
  Constant40/1 -> Relational Operator21/2
  Switch6/1 -> Switch15/3
  Switch14/1 -> Switch6/3
  Constant38/1 -> Relational Operator19/2
  Relational Operator19/1 -> Switch14/2
  Constant41/1 -> Switch14/1
  Logical Operator2/1 -> Switch8/2
  Data Type Conversion6/1 -> Relational Operator13/1, Relational Operator11/1, Relational Operator33/1, Relational Operator9/1, Relational Operator12/1, Relational Operator17/1, Relational Operator20/1
  Switch15/1 -> Switch7/3
  Constant49/1 -> Relational Operator30/2
  Relational Operator30/1 -> Switch15/2
  Constant50/1 -> Switch15/1
  Constant31/1 -> Relational Operator20/2
  Relational Operator20/1 -> Logical Operator4/1
  Logical Operator4/1 -> Switch6/2
  Constant51/1 -> Relational Operator31/2
  Relational Operator31/1 -> Logical Operator2/3
  CMS_GcCMS_ChgSOCset_pct/1 -> GcCMS_ChgSOCset_pct/1  "GcCMS_ChgSOCset_pct"
  Data Type Conversion14/1 -> CMS_GcCMS_ChgSOCset_pct/1
  CMS_GeCMS_AppChgMode_enum/1 -> GeCMS_AppChgMode_enum/1  "GeCMS_AppChgMode_enum"
  Ground12/1 -> CMS_GeCMS_AppChgMode_enum/1
  GbISP_TFIsoResFltLevel2_flg/1 -> Logical Operator5/1
  GbISP_TFIsoHVoffResFltLevel2_flg/1 -> Logical Operator5/2
  GbISP_TFIsoResFltLevel1_flg/1 -> Logical Operator7/1
  GbISP_TFIsoHVoffResFltLevel1_flg/1 -> Logical Operator7/2
  Logical Operator5/1 -> Switch16/2
  Constant28/1 -> Switch16/1
  Logical Operator7/1 -> Switch17/2
  Switch17/1 -> Switch16/3
  Constant53/1 -> Switch17/1
  Constant54/1 -> Switch17/3
  Switch16/1 -> Data Type Conversion15/1
  Data Type Conversion15/1 -> CMS_GcCMS_IsoFault_enum/1
  Logical Operator8/1 -> Switch11/2
  Relational Operator14/1 -> Logical Operator8/2
  Constant55/1 -> Relational Operator14/2
  Relational Operator29/1 -> Switch2/2
  Constant47/1 -> Relational Operator29/2
  ? -> Relational Operator29/1  "GcSOC_DispSOC_pct"
  Constant48/1 -> Switch2/1
  Logical Operator9/1 -> Logical Operator3/1
  Relational Operator9/1 -> Logical Operator9/1
  Relational Operator33/1 -> Logical Operator9/2
  Constant57/1 -> Relational Operator33/2

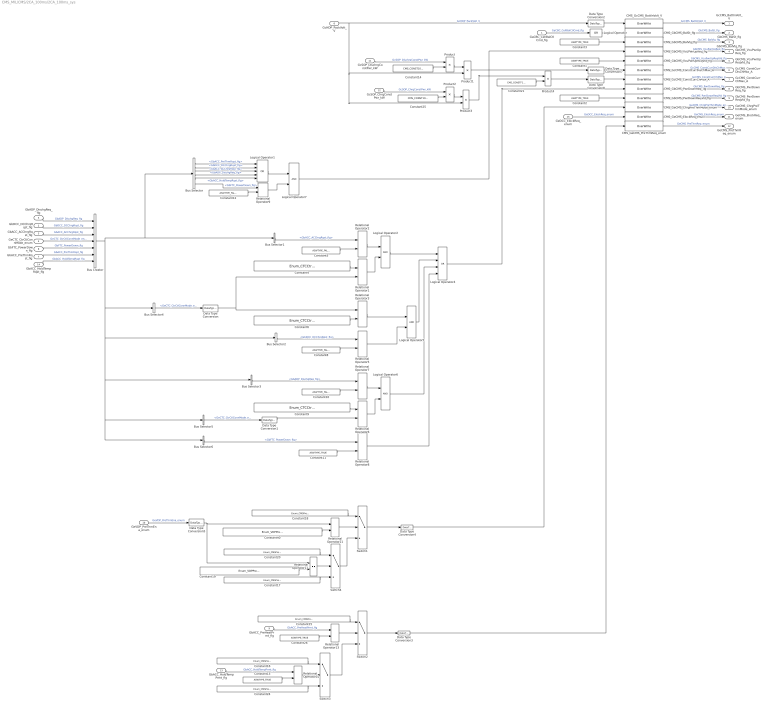
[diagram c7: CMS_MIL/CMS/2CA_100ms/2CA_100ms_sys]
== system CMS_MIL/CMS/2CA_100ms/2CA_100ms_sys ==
  GaCBC_CellBalCtlCmd_flg : Inport
  GbDCC_DCChrgRqst_flg : Inport  Port=2
  GbACC_ACChrgRqst_flg : Inport  Port=3
  GeCTC_CtrCtlConnMode_enum : Inport  Port=4
  GbADP_DischgReq_flg : Inport  Port=5
  GcHDP_PackVolt_V : Inport  Port=6
  GbACC_PreThmRqst_flg : Inport  Port=7
  GbFTC_PowerDown_flg : Inport  Port=8
  GbACC_PreHeatPrmt_flg : Inport  Port=9
  GeVDP_PreThmEna_enum : Inport  Port=10
  GcSOP_DischrgConstPwr_kW : Inport  Port=11
  GcSOP_ChrgConstPwr_kW : Inport  Port=12
  GbACC_HoldTempPrmt_flg : Inport  Port=13
  GbACC_HoldTempRqst_flg : Inport  Port=14
  GeDCC_ElockReq_enum : Inport  Port=15
  Bus Creator : BusCreator  Inputs=7
  Bus Selector : BusSelector  OutputSignals=GbACC_PreThmRqst_flg,GbDCC_DCChrgRqst_flg,GbACC_ACChrgRqst_flg,GbADP_DischgReq_flg,GbACC_HoldTempRqst_flg,GbFTC_PowerDown_flg
  Bus Selector1 : BusSelector  OutputSignals=GbACC_ACChrgRqst_flg
  Bus Selector2 : BusSelector  OutputSignals=GbDCC_DCChrgRqst_flg
  Bus Selector3 : BusSelector  OutputSignals=GbADP_DischgReq_flg
  Bus Selector4 : BusSelector  OutputSignals=GeCTC_CtrCtlConnMode_enum
  Bus Selector5 : BusSelector  OutputSignals=GeCTC_CtrCtlConnMode_enum
  Bus Selector6 : BusSelector  OutputSignals=GbFTC_PowerDown_flg
  CMS_GbCMS_BalSt_flg : AIWAYS_Powertrain_BMS_lib/Signals/OverWrite  OverWrite_Value=CbCMS_BalStOvr_flg  OverWrite_flag=CbCMS_BalStOvrSwt_flg
  CMS_GbCMS_BalVlg_flg : AIWAYS_Powertrain_BMS_lib/Signals/OverWrite  OverWrite_Value=CbCMS_BalVlgOvr_flg  OverWrite_flag=CbCMS_BalVlgOvrSwt_flg
  CMS_GbCMS_PwrDownReqVld_flg : AIWAYS_Powertrain_BMS_lib/Signals/OverWrite  OverWrite_Value=CbCMS_PwrDownReqVldOvr_flg  OverWrite_flag=CbCMS_PwrDownReqVldOvrSwt_flg
  CMS_GbCMS_PwrDownReq_flg : AIWAYS_Powertrain_BMS_lib/Signals/OverWrite  OverWrite_Value=CbCMS_PwrDownReqOvr_flg  OverWrite_flag=CbCMS_PwrDownReqOvrSwt_flg
  CMS_GbCMS_VcuPwrUpReqVld_flg : AIWAYS_Powertrain_BMS_lib/Signals/OverWrite  OverWrite_Value=CbCMS_VcuPwrUpReqVldOvr_flg  OverWrite_flag=CbCMS_VcuPwrUpReqVldOvrSwt_flg
  CMS_GbCMS_VcuPwrUpReq_flg : AIWAYS_Powertrain_BMS_lib/Signals/OverWrite  OverWrite_Value=CbCMS_VcuPwrUpReqOvr_flg  OverWrite_flag=CbCMS_VcuPwrUpReqOvrSwt_flg
  CMS_GcCMS_BattInVolt_V : AIWAYS_Powertrain_BMS_lib/Signals/OverWrite  OverWrite_Value=CcCMS_BattInVoltOvr_V  OverWrite_flag=CbCMS_BattInVoltOvrSwt_flg
  CMS_GcCMS_ConstCurrChMax_A : AIWAYS_Powertrain_BMS_lib/Signals/OverWrite  OverWrite_Value=CcCMS_ConstCurrChMaxOvr_A  OverWrite_flag=CbCMS_ConstCurrChMaxOvrSwt_flg
  CMS_GcCMS_ConstCurrDisChMax_A : AIWAYS_Powertrain_BMS_lib/Signals/OverWrite  OverWrite_Value=CcCMS_ConstCurrDisChMaxOvr_A  OverWrite_flag=CbCMS_ConstCurrDisChMaxOvrSwt_flg
  CMS_GeCMS_ChrgPreThmMode_enum : AIWAYS_Powertrain_BMS_lib/Signals/OverWrite  OverWrite_Value=CeCMS_ChrgPreThmModeOvr_enum  OverWrite_flag=CbCMS_ChrgPreThmModeOvrSwt_flg
  CMS_GeCMS_ElockReq_enum : AIWAYS_Powertrain_BMS_lib/Signals/OverWrite  OverWrite_Value=CeCMS_ElockReqOvr_enum  OverWrite_flag=CbCMS_ElockReqOvrSwt_flg
  CMS_GeCMS_PreThmReq_enum : AIWAYS_Powertrain_BMS_lib/Signals/OverWrite  OverWrite_Value=CeCMS_PreThmReqOvr_enum  OverWrite_flag=CbCMS_PreThmReqOvrSwt_flg
  Constant{1..3,11,13,26} (6 alike) : Constant  Value=ASWTYPE_TRUE
  Constant{5,8,10,12} (4 alike) : Constant  Value=ASWTYPE_FALSE
  Constant14 : Constant  Value=CMS_CONST1000_NUMB
  Constant15 : Constant  Value=Enum_CMSPreThmReq.Enum_CMSPreThmReq_PreHeatReq
  Constant16 : Constant  Value=Enum_CMSPreThmReq.Enum_CMSPreThmReq_HoldTempReq
  Constant17 : Constant  Value=Enum_CMSPreThmMode.Enum_CMSPreThmMode_Default
  Constant18 : Constant  Value=Enum_CMSPreThmMode.Enum_CMSPreThmMode_AChrgPreHeat
  Constant19 : Constant  Value=Enum_VDPPreThmEna.Enum_VDPPreThmEna_HoldtempEna
  Constant20 : Constant  Value=Enum_CMSPreThmMode.Enum_CMSPreThmMode_HoldTemp
  Constant21 : Constant  Value=CMS_CONSTF1_NUMB
  Constant24 : Constant  Value=Enum_CMSPreThmReq.Enum_CMSPreThmReq_Default
  Constant25 : Constant  Value=CMS_CONST1000_NUMB
  Constant4 : Constant  Value=Enum_CTCCtrCtlConnMode.Enum_CTCCtrCtlConnMode_ACChrg
  Constant40 : Constant  Value=Enum_VDPPreThmEna.Enum_VDPPreThmEna_PreHeatEna
  Constant6 : Constant  Value=Enum_CTCCtrCtlConnMode.Enum_CTCCtrCtlConnMode_DCChrg
  Constant9 : Constant  Value=Enum_CTCCtrCtlConnMode.Enum_CTCCtrCtlConnMode_VTX
  Data Type Conversion{,1..5,7..8} (8 alike) : DataTypeConversion
  Logical Operator : Logic  Operator=OR  Inputs=1  AllPortsSameDT=off  OutDataTypeStr=boolean
  Logical Operator1 : Logic  Operator=OR  Inputs=5  AllPortsSameDT=off  OutDataTypeStr=boolean
  Logical Operator{2,5..7} (4 alike) : Logic  AllPortsSameDT=off  OutDataTypeStr=boolean
  Logical Operator4 : Logic  Operator=OR  Inputs=4  AllPortsSameDT=off  OutDataTypeStr=boolean
  Product : Product  OutDataTypeStr=Inherit: Inherit via back propagation
  Product1 : Product  Inputs=*/  OutDataTypeStr=Inherit: Inherit via back propagation
  Product2 : Product  OutDataTypeStr=Inherit: Inherit via back propagation
  Product3 : Product  Inputs=*/  OutDataTypeStr=Inherit: Inherit via back propagation
  Product4 : Product  OutDataTypeStr=Inherit: Inherit via back propagation
  Relational Operator{1..3,5..11,13,21} (12 alike) : RelationalOperator  Operator===  OutDataTypeStr=boolean
  Switch{1..4} (4 alike) : Switch  Criteria=u2 ~= 0  Threshold=1  RndMeth=Zero
  GcCMS_BattInVolt_V : Outport
  GbCMS_BalSt_flg : Outport  Port=2
  GbCMS_BalVlg_flg : Outport  Port=3
  GbCMS_VcuPwrUpReq_flg : Outport  Port=4
  GbCMS_VcuPwrUpReqVld_flg : Outport  Port=5
  GcCMS_ConstCurrDisChMax_A : Outport  Port=6
  GcCMS_ConstCurrChMax_A : Outport  Port=7
  GbCMS_PwrDownReq_flg : Outport  Port=8
  GbCMS_PwrDownReqVld_flg : Outport  Port=9
  GeCMS_ChrgPreThmMode_enum : Outport  Port=10
  GeCMS_ElockReq_enum : Outport  Port=11
  GeCMS_PreThmReq_enum : Outport  Port=12
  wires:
  CMS_GcCMS_BattInVolt_V/1 -> GcCMS_BattInVolt_V/1  "GcCMS_BattInVolt_V"
  GcHDP_PackVolt_V/1 -> Product1/2, Product3/2, Data Type Conversion2/1  "GcHDP_PackVolt_V"
  CMS_GbCMS_BalSt_flg/1 -> GbCMS_BalSt_flg/1  "GbCMS_BalSt_flg"
  CMS_GeCMS_PreThmReq_enum/1 -> GeCMS_PreThmReq_enum/1  "GeCMS_PreThmReq_enum"
  CMS_GeCMS_ElockReq_enum/1 -> GeCMS_ElockReq_enum/1  "GeCMS_ElockReq_enum"
  CMS_GeCMS_ChrgPreThmMode_enum/1 -> GeCMS_ChrgPreThmMode_enum/1  "GeCMS_ChrgPreThmMode_enum"
  CMS_GbCMS_PwrDownReqVld_flg/1 -> GbCMS_PwrDownReqVld_flg/1  "GbCMS_PwrDownReqVld_flg"
  CMS_GbCMS_PwrDownReq_flg/1 -> GbCMS_PwrDownReq_flg/1  "GbCMS_PwrDownReq_flg"
  CMS_GcCMS_ConstCurrChMax_A/1 -> GcCMS_ConstCurrChMax_A/1  "GcCMS_ConstCurrChMax_A"
  CMS_GcCMS_ConstCurrDisChMax_A/1 -> GcCMS_ConstCurrDisChMax_A/1  "GcCMS_ConstCurrDisChMax_A"
  CMS_GbCMS_VcuPwrUpReqVld_flg/1 -> GbCMS_VcuPwrUpReqVld_flg/1  "GbCMS_VcuPwrUpReqVld_flg"
  CMS_GbCMS_VcuPwrUpReq_flg/1 -> GbCMS_VcuPwrUpReq_flg/1  "GbCMS_VcuPwrUpReq_flg"
  CMS_GbCMS_BalVlg_flg/1 -> GbCMS_BalVlg_flg/1  "GbCMS_BalVlg_flg"
  Data Type Conversion4/1 -> CMS_GeCMS_ChrgPreThmMode_enum/1
  Constant2/1 -> CMS_GbCMS_PwrDownReqVld_flg/1
  GaCBC_CellBalCtlCmd_flg/1 -> Logical Operator/1  "GaCBC_CellBalCtlCmd_flg"
  Logical Operator/1 -> CMS_GbCMS_BalSt_flg/1
  Constant3/1 -> CMS_GbCMS_BalVlg_flg/1
  GbDCC_DCChrgRqst_flg/1 -> Bus Creator/2  "GbDCC_DCChrgRqst_flg"
  Constant1/1 -> CMS_GbCMS_VcuPwrUpReqVld_flg/1
  Logical Operator4/1 -> CMS_GbCMS_PwrDownReq_flg/1
  Product3/1 -> Product4/1
  Data Type Conversion7/1 -> CMS_GcCMS_ConstCurrDisChMax_A/1
  Bus Creator/1 -> Bus Selector1/1, Bus Selector/1, Bus Selector6/1, Bus Selector5/1, Bus Selector3/1, Bus Selector2/1, Bus Selector4/1
  Bus Selector/2 -> Logical Operator1/2  "<GbDCC_DCChrgRqst_flg>"
  Bus Selector/3 -> Logical Operator1/3  "<GbACC_ACChrgRqst_flg>"
  Logical Operator1/1 -> Logical Operator7/1
  Bus Selector1/1 -> Relational Operator2/1  "<GbACC_ACChrgRqst_flg>"
  GeCTC_CtrCtlConnMode_enum/1 -> Bus Creator/4  "GeCTC_CtrCtlConnMode_enum"
  Constant5/1 -> Relational Operator2/2
  Relational Operator2/1 -> Logical Operator2/1
  Relational Operator1/1 -> Logical Operator2/2
  Data Type Conversion/1 -> Relational Operator1/2, Relational Operator3/1
  Constant4/1 -> Relational Operator1/1
  Constant6/1 -> Relational Operator3/2
  Logical Operator2/1 -> Logical Operator4/1
  Constant8/1 -> Relational Operator5/2
  Bus Selector2/1 -> Relational Operator5/1  "<GbDCC_DCChrgRqst_flg>"
  Relational Operator5/1 -> Logical Operator5/2
  Relational Operator3/1 -> Logical Operator5/1
  Logical Operator5/1 -> Logical Operator4/2
  GeDCC_ElockReq_enum/1 -> CMS_GeCMS_ElockReq_enum/1  "GeDCC_ElockReq_enum"
  Data Type Conversion2/1 -> CMS_GcCMS_BattInVolt_V/1
  GbADP_DischgReq_flg/1 -> Bus Creator/1  "GbADP_DischgReq_flg"
  Bus Selector/4 -> Logical Operator1/4  "<GbADP_DischgReq_flg>"
  Logical Operator6/1 -> Logical Operator4/3
  Constant9/1 -> Relational Operator6/1
  Relational Operator6/1 -> Logical Operator6/2
  Constant10/1 -> Relational Operator7/2
  Bus Selector3/1 -> Relational Operator7/1  "<GbADP_DischgReq_flg>"
  Relational Operator7/1 -> Logical Operator6/1
  GbACC_ACChrgRqst_flg/1 -> Bus Creator/3  "GbACC_ACChrgRqst_flg"
  Bus Selector4/1 -> Data Type Conversion/1  "<GeCTC_CtrCtlConnMode_enum>"
  Bus Selector5/1 -> Data Type Conversion1/1  "<GeCTC_CtrCtlConnMode_enum>"
  Data Type Conversion1/1 -> Relational Operator6/2
  GbACC_PreThmRqst_flg/1 -> Bus Creator/6  "GbACC_PreThmRqst_flg"
  GbFTC_PowerDown_flg/1 -> Bus Creator/5  "GbFTC_PowerDown_flg"
  Bus Selector6/1 -> Relational Operator8/1  "<GbFTC_PowerDown_flg>"
  Constant11/1 -> Relational Operator8/2
  Relational Operator8/1 -> Logical Operator4/4
  Bus Selector/6 -> Relational Operator9/1  "<GbFTC_PowerDown_flg>"
  Constant12/1 -> Relational Operator9/2
  Relational Operator9/1 -> Logical Operator7/2
  Logical Operator7/1 -> CMS_GbCMS_VcuPwrUpReq_flg/1
  Bus Selector/1 -> Logical Operator1/1  "<GbACC_PreThmRqst_flg>"
  Constant15/1 -> Switch2/1
  Data Type Conversion3/1 -> CMS_GeCMS_PreThmReq_enum/1
  Switch2/1 -> Data Type Conversion3/1
  GbACC_PreHeatPrmt_flg/1 -> Relational Operator13/1  "GbACC_PreHeatPrmt_flg"
  Switch1/1 -> Data Type Conversion4/1
  Constant17/1 -> Switch4/3
  Constant18/1 -> Switch1/1
  GeVDP_PreThmEna_enum/1 -> Data Type Conversion5/1  "GeVDP_PreThmEna_enum"
  Constant40/1 -> Relational Operator21/2
  Relational Operator21/1 -> Switch1/2
  Relational Operator13/1 -> Switch2/2
  Constant24/1 -> Switch3/3
  GcSOP_DischrgConstPwr_kW/1 -> Product/1  "GcSOP_DischrgConstPwr_kW"
  GcSOP_ChrgConstPwr_kW/1 -> Product2/1  "GcSOP_ChrgConstPwr_kW"
  Product1/1 -> Data Type Conversion7/1
  Constant14/1 -> Product/2
  Product/1 -> Product1/1
  Constant25/1 -> Product2/2
  Product2/1 -> Product3/1
  Data Type Conversion8/1 -> CMS_GcCMS_ConstCurrChMax_A/1
  Constant26/1 -> Relational Operator13/2
  Constant13/1 -> Relational Operator10/2
  GbACC_HoldTempPrmt_flg/1 -> Relational Operator10/1  "GbACC_HoldTempPrmt_flg"
  Relational Operator10/1 -> Switch3/2
  Constant16/1 -> Switch3/1
  Switch3/1 -> Switch2/3
  Constant19/1 -> Relational Operator11/2
  Relational Operator11/1 -> Switch4/2
  Data Type Conversion5/1 -> Relational Operator11/1, Relational Operator21/1
  Switch4/1 -> Switch1/3
  Constant20/1 -> Switch4/1
  GbACC_HoldTempRqst_flg/1 -> Bus Creator/7  "GbACC_HoldTempRqst_flg"
  Bus Selector/5 -> Logical Operator1/5  "<GbACC_HoldTempRqst_flg>"
  Constant21/1 -> Product4/2
  Product4/1 -> Data Type Conversion8/1

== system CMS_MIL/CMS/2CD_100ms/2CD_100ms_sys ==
  GcSOP_DischrgPwr_kW : Inport
  GcSOP_ChrgPwr_kW : Inport  Port=2
  GcSOP_DischrgConstPwr_kW : Inport  Port=3
  GcSOP_ChrgConstPwr_kW : Inport  Port=4
  CMS_GcCMS_ConstPwrCh_Kw : AIWAYS_Powertrain_BMS_lib/Signals/OverWrite  OverWrite_Value=CcCMS_ConstPwrChOvr_Kw  OverWrite_flag=CbCMS_ConstPwrChOvrSwt_flg
  CMS_GcCMS_ConstPwrDisCh_Kw : AIWAYS_Powertrain_BMS_lib/Signals/OverWrite  OverWrite_Value=CcCMS_ConstPwrDisChOvr_Kw  OverWrite_flag=CbCMS_ConstPwrDisChOvrSwt_flg
  CMS_GcCMS_PeakPwrCh_Kw : AIWAYS_Powertrain_BMS_lib/Signals/OverWrite  OverWrite_Value=CcCMS_PeakPwrChOvr_Kw  OverWrite_flag=CbCMS_PeakPwrChOvrSwt_flg
  CMS_GcCMS_PeakPwrDisCh_Kw : AIWAYS_Powertrain_BMS_lib/Signals/OverWrite  OverWrite_Value=CcCMS_PeakPwrDisChOvr_Kw  OverWrite_flag=CbCMS_PeakPwrDisChOvrSwt_flg
  Data Type Conversion{,1..3} (4 alike) : DataTypeConversion
  GcCMS_PeakPwrDisCh_Kw : Outport
  GcCMS_PeakPwrCh_Kw : Outport  Port=2
  GcCMS_ConstPwrDisCh_Kw : Outport  Port=3
  GcCMS_ConstPwrCh_Kw : Outport  Port=4
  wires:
  CMS_GcCMS_PeakPwrDisCh_Kw/1 -> GcCMS_PeakPwrDisCh_Kw/1  "GcCMS_PeakPwrDisCh_Kw"
  CMS_GcCMS_PeakPwrCh_Kw/1 -> GcCMS_PeakPwrCh_Kw/1  "GcCMS_PeakPwrCh_Kw"
  CMS_GcCMS_ConstPwrDisCh_Kw/1 -> GcCMS_ConstPwrDisCh_Kw/1  "GcCMS_ConstPwrDisCh_Kw"
  CMS_GcCMS_ConstPwrCh_Kw/1 -> GcCMS_ConstPwrCh_Kw/1  "GcCMS_ConstPwrCh_Kw"
  GcSOP_DischrgPwr_kW/1 -> Data Type Conversion/1  "GcSOP_DischrgPwr_kW"
  GcSOP_ChrgPwr_kW/1 -> Data Type Conversion1/1  "GcSOP_ChrgPwr_kW"
  GcSOP_DischrgConstPwr_kW/1 -> Data Type Conversion2/1  "GcSOP_DischrgConstPwr_kW"
  GcSOP_ChrgConstPwr_kW/1 -> Data Type Conversion3/1  "GcSOP_ChrgConstPwr_kW"
  Data Type Conversion/1 -> CMS_GcCMS_PeakPwrDisCh_Kw/1
  Data Type Conversion1/1 -> CMS_GcCMS_PeakPwrCh_Kw/1
  Data Type Conversion2/1 -> CMS_GcCMS_ConstPwrDisCh_Kw/1
  Data Type Conversion3/1 -> CMS_GcCMS_ConstPwrCh_Kw/1
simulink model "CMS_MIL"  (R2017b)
settings: Solver=FixedStepDiscrete  StartTime=0.0  StopTime=10.0  FixedStep=0.01  RelTol=1e-3  EnableMultiTasking=on
undefined symbols (not defined in the file): ASWTYPE_FALSE, ASWTYPE_TRUE, CcCMS_CANSendDelay_ms, CcCMS_ChrgMaxPackVoltLimt_V, CcCMS_ChrgRemTimeDftValDelayTime_ms, CcCMS_GBChgModeStayInCloseStatus_ms, CcCMS_PeakVoltCh_V, CcCMS_PeakVoltDisCh_V, CcSOC_DispSOCHighThrhd_pct, CMS09D_RUNTIME_MS, CMS_CONST0_NUMB, CMS_CONST1000_NUMB, CMS_CONST100_NUMB, CMS_CONST1_NUMB, CMS_CONST2047_NUMB, CMS_CONST2_NUMB, CMS_CONST3_NUMB, CMS_CONST4_NUMB, CMS_CONST5_NUMB, CMS_CONST6_NUMB, CMS_CONST7_NUMB, CMS_CONSTF1_NUMB, Enum_ACCACChrgState, Enum_CMSACChgMode, Enum_CMSBmsSelfChk, Enum_CMSBmsSt, Enum_CMSChgMode, Enum_CMSDCChgMode, Enum_CMSHVBatFltSevrtyStat, Enum_CMSHVConnSt, Enum_CMSPreThmMode, Enum_CMSPreThmReq, Enum_CTCCtrCtlConnMode, Enum_CTCCtrCtlState, Enum_DCCDCChrgState, Enum_DCCDCConnSt, Enum_ISOHVIsoFltLevel, Enum_LDPChrgGunState, Enum_MSMBMUState, Enum_ODPCCState, Enum_UDSAreaSel, Enum_VDPPreThmEna
libraries: AIWAYS_Powertrain_BMS_lib x156
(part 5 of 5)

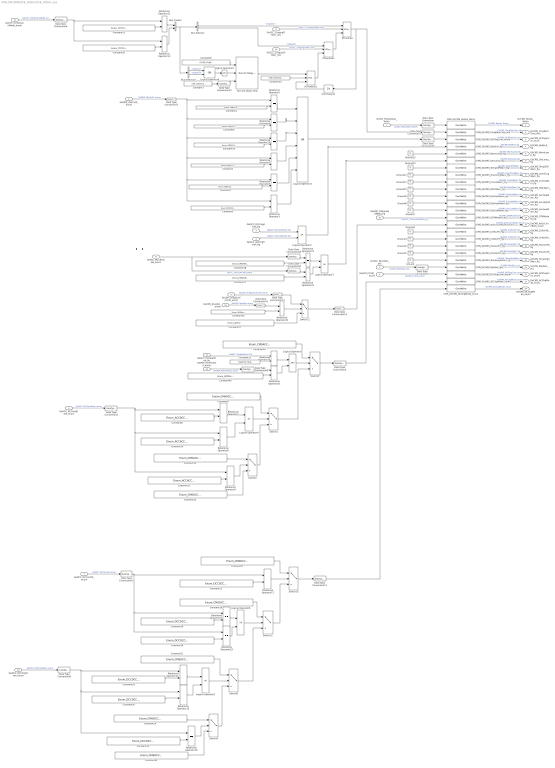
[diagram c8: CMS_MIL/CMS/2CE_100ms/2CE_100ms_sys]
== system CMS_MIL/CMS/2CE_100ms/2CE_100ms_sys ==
  note: 四级故障或三级故障
  GcISO_HVIsoValue_kohm : Inport
  GeODP_ObcCcSt_enum : Inport  Port=2
  GbDCC_DCChrgFinish_flg : Inport  Port=3
  GbACC_ACChrgFinish_flg : Inport  Port=4
  GcSOC_PackSOC_pct : Inport  Port=5
  GeACC_ACChrgState_enum : Inport  Port=6
  GeDCC_DCConnSt_enum : Inport  Port=7
  GeLDP_CC2St_enum : Inport  Port=8
  GcACC_ChrgingTiRem_min : Inport  Port=9
  GcDCC_ChrgingTiRem_min : Inport  Port=10
  GeCTC_CtrCtlConnMode_enum : Inport  Port=11
  GbACC_PreHeatPrmt_flg : Inport  Port=12
  GeVDP_PreThmEna_enum : Inport  Port=13
  GeDCC_DCChrgState_enum : Inport  Port=14
  GeLDP_ChrgGunConnSt_enum : Inport  Port=15
  GbADP_OTAmodeONReq_flg : Inport  Port=16
  GeFTC_FltLvlOnCAN_enum : Inport  Port=17
  GeUDS_AreaSel_enum : Inport  Port=18
  Bus Creator : BusCreator  Inputs=2
  Bus Selector : BusSelector  OutputSignals=signal1,signal2
  Bus Selector2 : BusSelector  OutputSignals=signal1,signal2
  CMS_GbCMS_BattFull_flg : AIWAYS_Powertrain_BMS_lib/Signals/OverWrite  OverWrite_Value=CbCMS_BattFullOvr_flg  OverWrite_flag=CbCMS_BattFullOvrSwt_flg
  CMS_GbCMS_CellOvFlt_flg : AIWAYS_Powertrain_BMS_lib/Signals/OverWrite  OverWrite_Value=CbCMS_CellOvFltOvr_flg  OverWrite_flag=CbCMS_CellOvFltOvrSwt_flg
  CMS_GbCMS_CellUvFlt_flg : AIWAYS_Powertrain_BMS_lib/Signals/OverWrite  OverWrite_Value=CbCMS_CellUvFltOvr_flg  OverWrite_flag=CbCMS_CellUvFltOvrSwt_flg
  CMS_GbCMS_ConsisWarn_flg : AIWAYS_Powertrain_BMS_lib/Signals/OverWrite  OverWrite_Value=CbCMS_ConsisWarnOvr_flg  OverWrite_flag=CbCMS_ConsisWarnOvrSwt_flg
  CMS_GbCMS_MishWarn_flg : AIWAYS_Powertrain_BMS_lib/Signals/OverWrite  OverWrite_Value=CbCMS_MishWarnOvr_flg  OverWrite_flag=CbCMS_MishWarnOvrSwt_flg
  CMS_GbCMS_OTAModeSt_flg : AIWAYS_Powertrain_BMS_lib/Signals/OverWrite  OverWrite_Value=CbCMS_OTAModeStOvr_flg  OverWrite_flag=CbCMS_OTAModeStOvrSwt_flg
  CMS_GbCMS_OverChrgWarn_flg : AIWAYS_Powertrain_BMS_lib/Signals/OverWrite  OverWrite_Value=CbCMS_OverChrgWarnOvr_flg  OverWrite_flag=CbCMS_OverChrgWarnOvrSwt_flg
  CMS_GbCMS_PackOvFlt_flg : AIWAYS_Powertrain_BMS_lib/Signals/OverWrite  OverWrite_Value=CbCMS_PackOvFltOvr_flg  OverWrite_flag=CbCMS_PackOvFltOvrSwt_flg
  CMS_GbCMS_PackUvFlt_flg : AIWAYS_Powertrain_BMS_lib/Signals/OverWrite  OverWrite_Value=CbCMS_PackUvFltOvr_flg  OverWrite_flag=CbCMS_PackUvFltOvrSwt_flg
  CMS_GbCMS_SerLamp_flg : AIWAYS_Powertrain_BMS_lib/Signals/OverWrite  OverWrite_Value=CbCMS_SerLampOvr_flg  OverWrite_flag=CbCMS_SerLampOvrSwt_flg
  CMS_GbCMS_SocHighWarn_flg : AIWAYS_Powertrain_BMS_lib/Signals/OverWrite  OverWrite_Value=CbCMS_SocHighWarnOvr_flg  OverWrite_flag=CbCMS_SocHighWarnOvrSwt_flg
  CMS_GbCMS_SocHopWarn_flg : AIWAYS_Powertrain_BMS_lib/Signals/OverWrite  OverWrite_Value=CbCMS_SocHopWarnOvr_flg  OverWrite_flag=CbCMS_SocHopWarnOvrSwt_flg
  CMS_GbCMS_SocLowWarn_flg : AIWAYS_Powertrain_BMS_lib/Signals/OverWrite  OverWrite_Value=CbCMS_SocLowWarnOvr_flg  OverWrite_flag=CbCMS_SocLowWarnOvrSwt_flg
  CMS_GbCMS_TempDiffWarn_flg : AIWAYS_Powertrain_BMS_lib/Signals/OverWrite  OverWrite_Value=CbCMS_TempDiffWarnOvr_flg  OverWrite_flag=CbCMS_TempDiffWarnOvrSwt_flg
  CMS_GbCMS_TempHighWarn_flg : AIWAYS_Powertrain_BMS_lib/Signals/OverWrite  OverWrite_Value=CbCMS_TempHighWarnOvr_flg  OverWrite_flag=CbCMS_TempHighWarnOvrSwt_flg
  CMS_GbCMS_WarnLamp_flg : AIWAYS_Powertrain_BMS_lib/Signals/OverWrite  OverWrite_Value=CbCMS_WarnLampOvr_flg  OverWrite_flag=CbCMS_WarnLampOvrSwt_flg
  CMS_GcCMS_ChrgRemTime_Min : AIWAYS_Powertrain_BMS_lib/Signals/OverWrite  OverWrite_Value=CcCMS_ChrgRemTimeOvr_Min  OverWrite_flag=CbCMS_ChrgRemTimeOvrSwt_flg
  CMS_GcCMS_RealSoc_pct : AIWAYS_Powertrain_BMS_lib/Signals/OverWrite  OverWrite_Value=CcCMS_RealSocOvr_pct  OverWrite_flag=CbCMS_RealSocOvrSwt_flg
  CMS_GcCMS_ResIso_Kohm : AIWAYS_Powertrain_BMS_lib/Signals/OverWrite  OverWrite_Value=CcCMS_ResIsoOvr_Kohm  OverWrite_flag=CbCMS_ResIsoOvrSwt_flg
  CMS_GeCMS_ACChgMode_enum : AIWAYS_Powertrain_BMS_lib/Signals/OverWrite  OverWrite_Value=CeCMS_ACChgModeOvr_enum  OverWrite_flag=CbCMS_ACChgModeOvrSwt_flg
  CMS_GeCMS_ACPlugCnnt_enum : AIWAYS_Powertrain_BMS_lib/Signals/OverWrite  OverWrite_Value=CeCMS_ACPlugCnntOvr_enum  OverWrite_flag=CbCMS_ACPlugCnntOvrSwt_flg
  CMS_GeCMS_AcDcConnBoth_enum : AIWAYS_Powertrain_BMS_lib/Signals/OverWrite  OverWrite_Value=CeCMS_AcDcConnBothOvr_enum  OverWrite_flag=CbCMS_AcDcConnBothOvrSwt_flg
  CMS_GeCMS_DCChgMode_enum : AIWAYS_Powertrain_BMS_lib/Signals/OverWrite  OverWrite_Value=CeCMS_DCChgModeOvr_enum  OverWrite_flag=CbCMS_DCChgModeOvrSwt_flg
  CMS_GeCMS_DCPlugConn_enum : AIWAYS_Powertrain_BMS_lib/Signals/OverWrite  OverWrite_Value=CeCMS_DCPlugConnOvr_enum  OverWrite_flag=CbCMS_DCPlugConnOvrSwt_flg
  Constant1 : Constant  Value=Enum_ODPCCState.Enum_ODPCCState_DisChrgConnect10A2700
  Constant10 : Constant  Value=Enum_ACCACChrgState.Enum_ACCACChrgState_StepChrg
  Constant11 : Constant  Value=Enum_ACCACChrgState.Enum_ACCACChrgState_Stop
  Constant12 : Constant  Value=Enum_CMSACChgMode.Enum_CMSACChgMode_ChrgEnd
  Constant14 : Constant  Value=Enum_ODPCCState.Enum_ODPCCState_ChrgConnect32A220
  Constant15 : Constant  Value=CMS_CONST2047_NUMB
  Constant16 : Constant  Value=Enum_CMSACChgMode.Enum_CMSACChgMode_PreHeat
  Constant17 : Constant  Value=Enum_CMSHVBatFltSevrtyStat.Enum_CMSHVBatFltSevrtyStat_High
  Constant18 : Constant  Value=Enum_CMSHVBatFltSevrtyStat.Enum_CMSHVBatFltSevrtyStat_Highest
  Constant19 : Constant  Value=Enum_DCCDCChrgState.Enum_DCCDCChrgState_Chrg  VectorParams1D=off
  Constant2 : Constant  Value=Enum_ODPCCState.Enum_ODPCCState_DisChrgConnect16A2000
  Constant20 : Constant  Value=Enum_DCCDCChrgState.Enum_DCCDCChrgState_StepChrg  VectorParams1D=off
  Constant21 : Constant  Value=Enum_CMSDCChgMode.Enum_CMSDCChgMode_Chging
  Constant22 : Constant  Value=Enum_DCCDCChrgState.Enum_DCCDCChrgState_Stop  VectorParams1D=off
  Constant23 : Constant  Value=Enum_CTCCtrCtlConnMode.Enum_CTCCtrCtlConnMode_ACChrg
  Constant24 : Constant  Value=Enum_CMSDCChgMode.Enum_CMSDCChgMode_ChgEnd
  Constant25 : Constant  Value=Enum_DCCDCConnSt.Enum_DCCDCConnSt_HandShake
  Constant26 : Constant  Value=Enum_CTCCtrCtlConnMode.Enum_CTCCtrCtlConnMode_DCChrg
  Constant27 : Constant  Value=Enum_CMSDCChgMode.Enum_CMSDCChgMode_HandOver
  Constant28 : Constant  Value=Enum_CMSDCChgMode.Enum_CMSDCChgMode_ParaConfig
  Constant29 : Constant  Value=Enum_DCCDCConnSt.Enum_DCCDCConnSt_ID
  Constant3 : Constant  Value=Enum_ODPCCState.Enum_ODPCCState_DisChrgConnect32A1000
  Constant30 : Constant  Value=Enum_DCCDCConnSt.Enum_DCCDCConnSt_CFG
  Constant31 : Constant  Value=ASWTYPE_TRUE
  Constant32 : Constant  Value=Enum_CMSDCChgMode.Enum_CMSDCChgMode_Default
  Constant33 : Constant  Value=Enum_CMSACChgMode.Enum_CMSACChgMode_Default
  Constant35 : Constant  Value=Enum_UDSAreaSel.Enum_UDSAreaSel_CN
  Constant37 : Constant  Value=Enum_LDPChrgGunState.Enum_LDPChrgGunState_NOTCONNECT
  Constant4 : Constant  Value=Enum_ODPCCState.Enum_ODPCCState_ChrgConnect10A1500
  Constant40 : Constant  Value=Enum_VDPPreThmEna.Enum_VDPPreThmEna_PreHeatEna
  Constant5 : Constant  Value=Enum_ODPCCState.Enum_ODPCCState_ChrgConnect16A680
  Constant6 : Constant  Value=CcCMS_ChrgRemTimeDftValDelayTime_ms
  Constant7 : Constant  Value=CMS_CONST100_NUMB
  Constant8 : Constant  Value=Enum_ACCACChrgState.Enum_ACCACChrgState_Chrg
  Constant9 : Constant  Value=Enum_CMSACChgMode.Enum_CMSACChgMode_Chrging
  Data Type Conversion{,1..16,18} (18 alike) : DataTypeConversion
  Ground{,1..4,7..13,15} (13 alike) : Ground
  IfThenElse : AIWAYS_Powertrain_BMS_lib/Signals/IfThenElse
  IfThenElse1 : AIWAYS_Powertrain_BMS_lib/Signals/IfThenElse
  IfThenElse2 : AIWAYS_Powertrain_BMS_lib/Signals/IfThenElse
  Logical Operator1 : Logic  Operator=OR  Inputs=6  AllPortsSameDT=off  OutDataTypeStr=boolean
  Logical Operator{2,4..8} (6 alike) : Logic  Operator=OR  AllPortsSameDT=off  OutDataTypeStr=boolean
  Logical Operator3 : Logic  AllPortsSameDT=off  OutDataTypeStr=boolean
  Logical Operator9 : Logic  Operator=NOT  AllPortsSameDT=off  OutDataTypeStr=boolean
  Relational Operator{1..3,5..11,13..24} (22 alike) : RelationalOperator  Operator===  OutDataTypeStr=boolean
  Switch{1..2,6,8..11} (7 alike) : Switch  Criteria=u2 ~= 0
  Switch12 : Switch  Criteria=u2 ~= 0  Threshold=1  RndMeth=Zero
  Turn On Delay Time : AIWAYS_Powertrain_BMS_lib/Delay Blocks/Turn On Delay Time
  Unit Delay21 : UnitDelay  SampleTime=-1  StateName=StateName
  GcCMS_ResIso_Kohm : Outport
  GcCMS_ChrgRemTime_Min : Outport  Port=2
  GeCMS_ACPlugCnnt_enum : Outport  Port=3
  GbCMS_BattFull_flg : Outport  Port=4
  GbCMS_WarnLamp_flg : Outport  Port=5
  GbCMS_SerLamp_flg : Outport  Port=6
  GbCMS_TempDiffWarn_flg : Outport  Port=7
  GbCMS_OverChrgWarn_flg : Outport  Port=8
  GbCMS_ConsisWarn_flg : Outport  Port=9
  GbCMS_MishWarn_flg : Outport  Port=10
  GbCMS_SocHopWarn_flg : Outport  Port=11
  GbCMS_SocHighWarn_flg : Outport  Port=12
  GbCMS_SocLowWarn_flg : Outport  Port=13
  GbCMS_OTAModeSt_flg : Outport  Port=14
  GeCMS_AcDcConnBoth_enum : Outport  Port=15
  GbCMS_CellUvFlt_flg : Outport  Port=16
  GbCMS_CellOvFlt_flg : Outport  Port=17
  GbCMS_PackUvFlt_flg : Outport  Port=18
  GbCMS_PackOvFlt_flg : Outport  Port=19
  GbCMS_TempHighWarn_flg : Outport  Port=20
  GcCMS_RealSoc_pct : Outport  Port=21
  GeCMS_DCPlugConn_enum : Outport  Port=22
  GeCMS_ACChgMode_enum : Outport  Port=23
  GeCMS_DCChgMode_enum : Outport  Port=24
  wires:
  CMS_GcCMS_ResIso_Kohm/1 -> GcCMS_ResIso_Kohm/1  "GcCMS_ResIso_Kohm"
  GcISO_HVIsoValue_kohm/1 -> Data Type Conversion/1  "GcISO_HVIsoValue_kohm"
  CMS_GcCMS_ChrgRemTime_Min/1 -> GcCMS_ChrgRemTime_Min/1  "GcCMS_ChrgRemTime_Min"
  GeDCC_DCConnSt_enum/1 -> Data Type Conversion10/1  "GeDCC_DCConnSt_enum"
  CMS_GeCMS_DCChgMode_enum/1 -> GeCMS_DCChgMode_enum/1  "GeCMS_DCChgMode_enum"
  CMS_GeCMS_ACChgMode_enum/1 -> GeCMS_ACChgMode_enum/1  "GeCMS_ACChgMode_enum"
  CMS_GeCMS_DCPlugConn_enum/1 -> GeCMS_DCPlugConn_enum/1  "GeCMS_DCPlugConn_enum"
  CMS_GcCMS_RealSoc_pct/1 -> GcCMS_RealSoc_pct/1  "GcCMS_RealSoc_pct"
  CMS_GbCMS_TempHighWarn_flg/1 -> GbCMS_TempHighWarn_flg/1  "GbCMS_TempHighWarn_flg"
  CMS_GbCMS_PackOvFlt_flg/1 -> GbCMS_PackOvFlt_flg/1  "GbCMS_PackOvFlt_flg"
  CMS_GbCMS_PackUvFlt_flg/1 -> GbCMS_PackUvFlt_flg/1  "GbCMS_PackUvFlt_flg"
  CMS_GbCMS_CellOvFlt_flg/1 -> GbCMS_CellOvFlt_flg/1  "GbCMS_CellOvFlt_flg"
  CMS_GbCMS_CellUvFlt_flg/1 -> GbCMS_CellUvFlt_flg/1  "GbCMS_CellUvFlt_flg"
  CMS_GeCMS_AcDcConnBoth_enum/1 -> GeCMS_AcDcConnBoth_enum/1  "GeCMS_AcDcConnBoth_enum"
  CMS_GbCMS_OTAModeSt_flg/1 -> GbCMS_OTAModeSt_flg/1  "GbCMS_OTAModeSt_flg"
  CMS_GbCMS_SocLowWarn_flg/1 -> GbCMS_SocLowWarn_flg/1  "GbCMS_SocLowWarn_flg"
  CMS_GbCMS_SocHighWarn_flg/1 -> GbCMS_SocHighWarn_flg/1  "GbCMS_SocHighWarn_flg"
  CMS_GbCMS_SocHopWarn_flg/1 -> GbCMS_SocHopWarn_flg/1  "GbCMS_SocHopWarn_flg"
  CMS_GbCMS_MishWarn_flg/1 -> GbCMS_MishWarn_flg/1  "GbCMS_MishWarn_flg"
  CMS_GbCMS_ConsisWarn_flg/1 -> GbCMS_ConsisWarn_flg/1  "GbCMS_ConsisWarn_flg"
  CMS_GbCMS_OverChrgWarn_flg/1 -> GbCMS_OverChrgWarn_flg/1  "GbCMS_OverChrgWarn_flg"
  CMS_GbCMS_TempDiffWarn_flg/1 -> GbCMS_TempDiffWarn_flg/1  "GbCMS_TempDiffWarn_flg"
  CMS_GbCMS_SerLamp_flg/1 -> GbCMS_SerLamp_flg/1  "GbCMS_SerLamp_flg"
  CMS_GbCMS_WarnLamp_flg/1 -> GbCMS_WarnLamp_flg/1  "GbCMS_WarnLamp_flg"
  CMS_GbCMS_BattFull_flg/1 -> GbCMS_BattFull_flg/1  "GbCMS_BattFull_flg"
  CMS_GeCMS_ACPlugCnnt_enum/1 -> GeCMS_ACPlugCnnt_enum/1  "GeCMS_ACPlugCnnt_enum"
  GeODP_ObcCcSt_enum/1 -> Data Type Conversion3/1  "GeODP_ObcCcSt_enum"
  GbDCC_DCChrgFinish_flg/1 -> Logical Operator2/1  "GbDCC_DCChrgFinish_flg"
  GbACC_ACChrgFinish_flg/1 -> Logical Operator2/2  "GbACC_ACChrgFinish_flg"
  Logical Operator2/1 -> CMS_GbCMS_BattFull_flg/1
  GeACC_ACChrgState_enum/1 -> Data Type Conversion2/1  "GeACC_ACChrgState_enum"
  GcSOC_PackSOC_pct/1 -> Data Type Conversion1/1  "GcSOC_PackSOC_pct"
  GeLDP_CC2St_enum/1 -> CMS_GeCMS_DCPlugConn_enum/1  "GeLDP_CC2St_enum"
  Ground/1 -> CMS_GbCMS_TempHighWarn_flg/1
  Ground1/1 -> CMS_GbCMS_PackOvFlt_flg/1
  Ground2/1 -> CMS_GbCMS_PackUvFlt_flg/1
  Ground3/1 -> CMS_GbCMS_CellOvFlt_flg/1
  Ground4/1 -> CMS_GbCMS_CellUvFlt_flg/1
  GeLDP_ChrgGunConnSt_enum/1 -> Data Type Conversion13/1  "GeLDP_ChrgGunConnSt_enum"
  GbADP_OTAmodeONReq_flg/1 -> CMS_GbCMS_OTAModeSt_flg/1  "GbADP_OTAmodeONReq_flg"
  Ground7/1 -> CMS_GbCMS_SocLowWarn_flg/1
  Ground8/1 -> CMS_GbCMS_SocHighWarn_flg/1
  Ground9/1 -> CMS_GbCMS_SocHopWarn_flg/1
  Ground10/1 -> CMS_GbCMS_MishWarn_flg/1
  Ground11/1 -> CMS_GbCMS_ConsisWarn_flg/1
  Ground12/1 -> CMS_GbCMS_OverChrgWarn_flg/1
  Ground13/1 -> CMS_GbCMS_TempDiffWarn_flg/1
  Logical Operator7/1 -> CMS_GbCMS_SerLamp_flg/1
  Ground15/1 -> CMS_GbCMS_WarnLamp_flg/1
  Data Type Conversion7/1 -> CMS_GcCMS_ChrgRemTime_Min/1
  Data Type Conversion/1 -> CMS_GcCMS_ResIso_Kohm/1
  Data Type Conversion1/1 -> CMS_GcCMS_RealSoc_pct/1
  Relational Operator10/1 -> Logical Operator1/3
  Relational Operator6/1 -> Logical Operator1/2
  Constant14/1 -> Relational Operator10/2
  Constant5/1 -> Relational Operator6/2
  Relational Operator5/1 -> Logical Operator1/1
  Constant4/1 -> Relational Operator5/2
  Constant1/1 -> Relational Operator1/2
  Constant2/1 -> Relational Operator2/2
  Data Type Conversion3/1 -> Relational Operator5/1, Relational Operator1/1, Relational Operator3/1, Relational Operator2/1, Relational Operator10/1, Relational Operator6/1
  Constant3/1 -> Relational Operator3/2
  Relational Operator1/1 -> Logical Operator1/4
  Relational Operator2/1 -> Logical Operator1/5
  Relational Operator3/1 -> Logical Operator1/6
  Logical Operator1/1 -> Data Type Conversion5/1
  Data Type Conversion2/1 -> Relational Operator7/1, Relational Operator9/1, Relational Operator8/1
  Constant8/1 -> Relational Operator7/2
  Relational Operator7/1 -> Logical Operator4/1
  Constant9/1 -> Switch1/1
  Logical Operator4/1 -> Switch1/2
  Constant10/1 -> Relational Operator8/2
  Relational Operator8/1 -> Logical Operator4/2
  Constant11/1 -> Relational Operator9/2
  Relational Operator9/1 -> Switch2/2
  Switch2/1 -> Switch1/3
  Constant12/1 -> Switch2/1
  Constant33/1 -> Switch2/3
  Data Type Conversion4/1 -> CMS_GeCMS_ACChgMode_enum/1
  Data Type Conversion5/1 -> CMS_GeCMS_ACPlugCnnt_enum/1
  Constant23/1 -> Relational Operator11/2
  GeCTC_CtrCtlConnMode_enum/1 -> Data Type Conversion6/1  "GeCTC_CtrCtlConnMode_enum"
  GcACC_ChrgingTiRem_min/1 -> IfThenElse/2  "GcACC_ChrgingTiRem_min"
  Constant26/1 -> Relational Operator13/2
  Data Type Conversion6/1 -> Relational Operator13/1, Relational Operator11/1
  GcDCC_ChrgingTiRem_min/1 -> IfThenElse1/2  "GcDCC_ChrgingTiRem_min"
  Constant40/1 -> Relational Operator21/2
  GbACC_PreHeatPrmt_flg/1 -> Relational Operator20/1  "GbACC_PreHeatPrmt_flg"
  GeVDP_PreThmEna_enum/1 -> Data Type Conversion9/1  "GeVDP_PreThmEna_enum"
  Constant31/1 -> Relational Operator20/2
  Data Type Conversion9/1 -> Relational Operator21/1
  Relational Operator21/1 -> Logical Operator3/2
  Relational Operator20/1 -> Logical Operator3/1
  Logical Operator3/1 -> Switch6/2
  Switch6/1 -> Data Type Conversion4/1
  Switch1/1 -> Switch6/3
  Constant16/1 -> Switch6/1
  GeDCC_DCChrgState_enum/1 -> Data Type Conversion8/1  "GeDCC_DCChrgState_enum"
  Relational Operator14/1 -> Logical Operator5/1
  Constant19/1 -> Relational Operator14/2
  Logical Operator5/1 -> Switch8/2
  Constant20/1 -> Relational Operator15/2
  Relational Operator15/1 -> Logical Operator5/2
  Constant21/1 -> Switch8/1
  Constant32/1 -> Switch9/3
  Constant24/1 -> Switch9/1
  Relational Operator16/1 -> Switch9/2
  Data Type Conversion8/1 -> Relational Operator16/1, Relational Operator15/1, Relational Operator14/1
  Switch9/1 -> Switch8/3
  Constant22/1 -> Relational Operator16/2
  Data Type Conversion10/1 -> Relational Operator17/1, Relational Operator19/1, Relational Operator18/1
  Constant25/1 -> Relational Operator17/2
  Relational Operator17/1 -> Switch10/2
  Constant27/1 -> Switch10/1
  Switch11/1 -> Switch10/3
  Constant28/1 -> Switch11/1
  Relational Operator18/1 -> Logical Operator6/1
  Constant29/1 -> Relational Operator18/2
  Logical Operator6/1 -> Switch11/2
  Relational Operator19/1 -> Logical Operator6/2
  Constant30/1 -> Relational Operator19/2
  Switch8/1 -> Switch11/3
  Switch10/1 -> Data Type Conversion11/1
  Data Type Conversion11/1 -> CMS_GeCMS_DCChgMode_enum/1
  GeFTC_FltLvlOnCAN_enum/1 -> Data Type Conversion16/1, Data Type Conversion18/1  "GeFTC_FltLvlOnCAN_enum"
  Relational Operator23/1 -> Logical Operator7/1
  Relational Operator22/1 -> Logical Operator7/2
  Constant35/1 -> Relational Operator24/2
  GeUDS_AreaSel_enum/1 -> Data Type Conversion12/1  "GeUDS_AreaSel_enum"
  Data Type Conversion12/1 -> Relational Operator24/1
  Relational Operator24/1 -> Switch12/2
  Constant37/1 -> Switch12/3
  Switch12/1 -> Data Type Conversion14/1
  Data Type Conversion13/1 -> Switch12/1
  Data Type Conversion14/1 -> CMS_GeCMS_AcDcConnBoth_enum/1
  IfThenElse1/1 -> IfThenElse/3
  Constant15/1 -> IfThenElse2/2
  IfThenElse/1 -> Unit Delay21/1, Data Type Conversion7/1
  Unit Delay21/1 -> IfThenElse2/3
  Turn On Delay Time/1 -> IfThenElse2/1
  IfThenElse2/1 -> IfThenElse1/3
  Relational Operator11/1 -> Bus Creator/1
  Relational Operator13/1 -> Bus Creator/2
  Bus Selector/1 -> IfThenElse/1  "<signal1>"
  Bus Selector/2 -> IfThenElse1/1  "<signal2>"
  Bus Creator/1 -> Bus Selector/1, Bus Selector2/1
  Logical Operator9/1 -> Turn On Delay Time/2
  Constant7/1 -> Data Type Conversion15/1
  Logical Operator8/1 -> Logical Operator9/1
  Constant6/1 -> Turn On Delay Time/1
  Bus Selector2/1 -> Logical Operator8/1  "<signal1>"
  Bus Selector2/2 -> Logical Operator8/2  "<signal2>"
  Data Type Conversion15/1 -> Turn On Delay Time/3
  Constant17/1 -> Relational Operator22/2
  Constant18/1 -> Relational Operator23/2
  Data Type Conversion18/1 -> Relational Operator23/1
  Data Type Conversion16/1 -> Relational Operator22/1

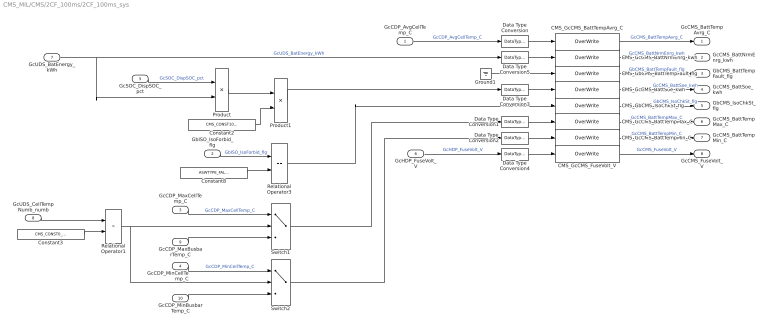
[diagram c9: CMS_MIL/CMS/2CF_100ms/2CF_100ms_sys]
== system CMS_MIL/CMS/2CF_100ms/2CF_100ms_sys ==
  GcCDP_AvgCellTemp_C : Inport
  GbISO_IsoForbid_flg : Inport  Port=2
  GcCDP_MaxCellTemp_C : Inport  Port=3
  GcCDP_MinCellTemp_C : Inport  Port=4
  GcSOC_DispSOC_pct : Inport  Port=5
  GcHDP_FuseVolt_V : Inport  Port=6
  GcUDS_BatEnergy_kWh : Inport  Port=7
  GcUDS_CellTempNumb_numb : Inport  Port=8
  GcCDP_MaxBusbarTemp_C : Inport  Port=9
  GcCDP_MinBusbarTemp_C : Inport  Port=10
  CMS_GbCMS_BattTempFault_flg : AIWAYS_Powertrain_BMS_lib/Signals/OverWrite  OverWrite_Value=CbCMS_BattTempFaultOvr_flg  OverWrite_flag=CbCMS_BattTempFaultOvrSwt_flg
  CMS_GbCMS_IsoChkSt_flg : AIWAYS_Powertrain_BMS_lib/Signals/OverWrite  OverWrite_Value=CbCMS_IsoChkStOvr_flg  OverWrite_flag=CbCMS_IsoChkStOvrSwt_flg
  CMS_GcCMS_BattNrmEnrg_kwh : AIWAYS_Powertrain_BMS_lib/Signals/OverWrite  OverWrite_Value=CcCMS_BattNrmEnrgOvr_kwh  OverWrite_flag=CbCMS_BattNrmEnrgOvrSwt_flg
  CMS_GcCMS_BattSoe_kwh : AIWAYS_Powertrain_BMS_lib/Signals/OverWrite  OverWrite_Value=CcCMS_BattSoeOvr_kwh  OverWrite_flag=CbCMS_BattSoeOvrSwt_flg
  CMS_GcCMS_BattTempAvrg_C : AIWAYS_Powertrain_BMS_lib/Signals/OverWrite  OverWrite_Value=CcCMS_BattTempAvrgOvr_C  OverWrite_flag=CbCMS_BattTempAvrgOvrSwt_flg
  CMS_GcCMS_BattTempMax_C : AIWAYS_Powertrain_BMS_lib/Signals/OverWrite  OverWrite_Value=CcCMS_BattTempMaxOvr_C  OverWrite_flag=CbCMS_BattTempMaxOvrSwt_flg
  CMS_GcCMS_BattTempMin_C : AIWAYS_Powertrain_BMS_lib/Signals/OverWrite  OverWrite_Value=CcCMS_BattTempMinOvr_C  OverWrite_flag=CbCMS_BattTempMinOvrSwt_flg
  CMS_GcCMS_FuseVolt_V : AIWAYS_Powertrain_BMS_lib/Signals/OverWrite  OverWrite_Value=CcCMS_FuseVoltOvr_V  OverWrite_flag=CbCMS_FuseVoltOvrSwt_flg
  Constant2 : Constant  Value=CMS_CONST100_NUMB
  Constant3 : Constant  Value=CMS_CONST0_NUMB
  Constant8 : Constant  Value=ASWTYPE_FALSE
  Data Type Conversion : DataTypeConversion  RndMeth=Round
  Data Type Conversion1 : DataTypeConversion  RndMeth=Round
  Data Type Conversion2 : DataTypeConversion  RndMeth=Round
  Data Type Conversion3 : DataTypeConversion
  Data Type Conversion4 : DataTypeConversion
  Data Type Conversion5 : DataTypeConversion
  Ground1 : Ground
  Product : Product  OutDataTypeStr=Inherit: Inherit via back propagation
  Product1 : Product  Inputs=*/  OutDataTypeStr=Inherit: Inherit via back propagation
  Relational Operator1 : RelationalOperator  Operator=>  OutDataTypeStr=boolean
  Relational Operator3 : RelationalOperator  Operator===  OutDataTypeStr=boolean
  Switch1 : Switch  Criteria=u2 ~= 0  Threshold=1  RndMeth=Zero
  Switch2 : Switch  Criteria=u2 ~= 0  Threshold=1  RndMeth=Zero
  GcCMS_BattTempAvrg_C : Outport
  GcCMS_BattNrmEnrg_kwh : Outport  Port=2
  GbCMS_BattTempFault_flg : Outport  Port=3
  GcCMS_BattSoe_kwh : Outport  Port=4
  GbCMS_IsoChkSt_flg : Outport  Port=5
  GcCMS_BattTempMax_C : Outport  Port=6
  GcCMS_BattTempMin_C : Outport  Port=7
  GcCMS_FuseVolt_V : Outport  Port=8
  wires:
  GcCDP_AvgCellTemp_C/1 -> Data Type Conversion/1  "GcCDP_AvgCellTemp_C"
  GcCDP_MinCellTemp_C/1 -> Switch2/1  "GcCDP_MinCellTemp_C"
  GcCDP_MaxCellTemp_C/1 -> Switch1/1  "GcCDP_MaxCellTemp_C"
  GbISO_IsoForbid_flg/1 -> Relational Operator3/1  "GbISO_IsoForbid_flg"
  Constant8/1 -> Relational Operator3/2
  CMS_GcCMS_BattTempAvrg_C/1 -> GcCMS_BattTempAvrg_C/1  "GcCMS_BattTempAvrg_C"
  CMS_GcCMS_BattTempMax_C/1 -> GcCMS_BattTempMax_C/1  "GcCMS_BattTempMax_C"
  CMS_GcCMS_BattTempMin_C/1 -> GcCMS_BattTempMin_C/1  "GcCMS_BattTempMin_C"
  CMS_GcCMS_BattNrmEnrg_kwh/1 -> GcCMS_BattNrmEnrg_kwh/1  "GcCMS_BattNrmEnrg_kwh"
  CMS_GbCMS_IsoChkSt_flg/1 -> GbCMS_IsoChkSt_flg/1  "GbCMS_IsoChkSt_flg"
  CMS_GcCMS_BattSoe_kwh/1 -> GcCMS_BattSoe_kwh/1  "GcCMS_BattSoe_kwh"
  CMS_GbCMS_BattTempFault_flg/1 -> GbCMS_BattTempFault_flg/1  "GbCMS_BattTempFault_flg"
  CMS_GcCMS_FuseVolt_V/1 -> GcCMS_FuseVolt_V/1  "GcCMS_FuseVolt_V"
  Relational Operator3/1 -> CMS_GbCMS_IsoChkSt_flg/1
  Ground1/1 -> CMS_GbCMS_BattTempFault_flg/1
  Data Type Conversion4/1 -> CMS_GcCMS_FuseVolt_V/1
  Data Type Conversion/1 -> CMS_GcCMS_BattTempAvrg_C/1
  Data Type Conversion1/1 -> CMS_GcCMS_BattTempMax_C/1
  Data Type Conversion2/1 -> CMS_GcCMS_BattTempMin_C/1
  GcSOC_DispSOC_pct/1 -> Product/1  "GcSOC_DispSOC_pct"
  Data Type Conversion3/1 -> CMS_GcCMS_BattSoe_kwh/1
  Product1/1 -> Data Type Conversion3/1
  Product/1 -> Product1/1
  Constant2/1 -> Product1/2
  GcHDP_FuseVolt_V/1 -> Data Type Conversion4/1  "GcHDP_FuseVolt_V"
  Data Type Conversion5/1 -> CMS_GcCMS_BattNrmEnrg_kwh/1
  GcUDS_BatEnergy_kWh/1 -> Product/2, Data Type Conversion5/1  "GcUDS_BatEnergy_kWh"
  Constant3/1 -> Relational Operator1/2
  Relational Operator1/1 -> Switch2/2, Switch1/2
  GcUDS_CellTempNumb_numb/1 -> Relational Operator1/1
  GcCDP_MaxBusbarTemp_C/1 -> Switch1/3
  Switch1/1 -> Data Type Conversion1/1
  GcCDP_MinBusbarTemp_C/1 -> Switch2/3
  Switch2/1 -> Data Type Conversion2/1

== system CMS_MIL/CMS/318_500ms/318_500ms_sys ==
  GcCDP_MaxCellVoltNumb_numb : Inport
  GcCDP_MinCellVoltNumb_numb : Inport  Port=2
  GcCDP_MaxCellTempNumb_numb : Inport  Port=3
  GcCDP_MinCellTempNumb_numb : Inport  Port=4
  GbWSM_DCWkUpPrs_flg : Inport  Port=5
  CMS_GbCMS_DChrgWkUp_flg : AIWAYS_Powertrain_BMS_lib/Signals/OverWrite  OverWrite_Value=CbCMS_DChrgWkUpOvr_flg  OverWrite_flag=CbCMS_DChrgWkUpOvrSwt_flg
  CMS_GcCMS_MaxCellTempNumb_numb : AIWAYS_Powertrain_BMS_lib/Signals/OverWrite  OverWrite_Value=CcCMS_MaxCellTempNumbOvr_numb  OverWrite_flag=CbCMS_MaxCellTempNumbOvrSwt_flg
  CMS_GcCMS_MaxCellVoltNumb_numb : AIWAYS_Powertrain_BMS_lib/Signals/OverWrite  OverWrite_Value=CcCMS_MaxCellVoltNumbOvr_numb  OverWrite_flag=CbCMS_MaxCellVoltNumbOvrSwt_flg
  CMS_GcCMS_MaxTempNumb_numb : AIWAYS_Powertrain_BMS_lib/Signals/OverWrite  OverWrite_Value=CcCMS_MaxTempNumbOvr_numb  OverWrite_flag=CbCMS_MaxTempNumbOvrSwt_flg
  CMS_GcCMS_MaxVoltNumb_numb : AIWAYS_Powertrain_BMS_lib/Signals/OverWrite  OverWrite_Value=CcCMS_MaxVoltNumbOvr_numb  OverWrite_flag=CbCMS_MaxVoltNumbOvrSwt_flg
  CMS_GcCMS_MinCellTempNumb_numb : AIWAYS_Powertrain_BMS_lib/Signals/OverWrite  OverWrite_Value=CcCMS_MinCellTempNumbOvr_numb  OverWrite_flag=CbCMS_MinCellTempNumbOvrSwt_flg
  CMS_GcCMS_MinCellVoltNumb_numb : AIWAYS_Powertrain_BMS_lib/Signals/OverWrite  OverWrite_Value=CcCMS_MinCellVoltNumbOvr_numb  OverWrite_flag=CbCMS_MinCellVoltNumbOvrSwt_flg
  CMS_GcCMS_MinTempNumb_numb : AIWAYS_Powertrain_BMS_lib/Signals/OverWrite  OverWrite_Value=CcCMS_MinTempNumbOvr_numb  OverWrite_flag=CbCMS_MinTempNumbOvrSwt_flg
  CMS_GcCMS_MinVoltNumb_numb : AIWAYS_Powertrain_BMS_lib/Signals/OverWrite  OverWrite_Value=CcCMS_MinVoltNumbOvr_numb  OverWrite_flag=CbCMS_MinVoltNumbOvrSwt_flg
  CMS_GeCMS_AChrgObsr_enum : AIWAYS_Powertrain_BMS_lib/Signals/OverWrite  OverWrite_Value=CeCMS_AChrgObsrOvr_enum  OverWrite_flag=CbCMS_AChrgObsrOvrSwt_flg
  CMS_GeCMS_DChrgModeDebug_enum : AIWAYS_Powertrain_BMS_lib/Signals/OverWrite  OverWrite_Value=CeCMS_DChrgModeDebugOvr_enum  OverWrite_flag=CbCMS_DChrgModeDebugOvrSwt_flg
  CMS_GeCMS_EvccMode_enum : AIWAYS_Powertrain_BMS_lib/Signals/OverWrite  OverWrite_Value=CeCMS_EvccModeOvr_enum  OverWrite_flag=CbCMS_EvccModeOvrSwt_flg
  CMS_GeCMS_PreThmObsvr_enum : AIWAYS_Powertrain_BMS_lib/Signals/OverWrite  OverWrite_Value=CeCMS_PreThmObsvrOvr_enum  OverWrite_flag=CbCMS_PreThmObsvrOvrSwt_flg
  Constant{1..3,15} (4 alike) : Constant  Value=CMS_CONST1_NUMB
  Ground{1..4} (4 alike) : Ground
  GcCMS_MaxCellVoltNumb_numb : Outport
  GcCMS_MinCellVoltNumb_numb : Outport  Port=2
  GcCMS_MaxCellTempNumb_numb : Outport  Port=3
  GcCMS_MinCellTempNumb_numb : Outport  Port=4
  GcCMS_MaxVoltNumb_numb : Outport  Port=5
  GcCMS_MinVoltNumb_numb : Outport  Port=6
  GcCMS_MaxTempNumb_numb : Outport  Port=7
  GcCMS_MinTempNumb_numb : Outport  Port=8
  GeCMS_DChrgModeDebug_enum : Outport  Port=9
  GbCMS_DChrgWkUp_flg : Outport  Port=10
  GeCMS_EvccMode_enum : Outport  Port=11
  GeCMS_AChrgObsr_enum : Outport  Port=12
  GeCMS_PreThmObsvr_enum : Outport  Port=13
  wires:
  Ground1/1 -> CMS_GeCMS_AChrgObsr_enum/1
  GcCDP_MaxCellVoltNumb_numb/1 -> CMS_GcCMS_MaxCellVoltNumb_numb/1  "GcCDP_MaxCellVoltNumb_numb"
  CMS_GcCMS_MaxCellVoltNumb_numb/1 -> GcCMS_MaxCellVoltNumb_numb/1  "GcCMS_MaxCellVoltNumb_numb"
  GcCDP_MinCellVoltNumb_numb/1 -> CMS_GcCMS_MinCellVoltNumb_numb/1  "GcCDP_MinCellVoltNumb_numb"
  GcCDP_MaxCellTempNumb_numb/1 -> CMS_GcCMS_MaxCellTempNumb_numb/1  "GcCDP_MaxCellTempNumb_numb"
  GcCDP_MinCellTempNumb_numb/1 -> CMS_GcCMS_MinCellTempNumb_numb/1  "GcCDP_MinCellTempNumb_numb"
  CMS_GcCMS_MinCellVoltNumb_numb/1 -> GcCMS_MinCellVoltNumb_numb/1  "GcCMS_MinCellVoltNumb_numb"
  CMS_GcCMS_MaxCellTempNumb_numb/1 -> GcCMS_MaxCellTempNumb_numb/1  "GcCMS_MaxCellTempNumb_numb"
  CMS_GcCMS_MinCellTempNumb_numb/1 -> GcCMS_MinCellTempNumb_numb/1  "GcCMS_MinCellTempNumb_numb"
  CMS_GcCMS_MaxVoltNumb_numb/1 -> GcCMS_MaxVoltNumb_numb/1  "GcCMS_MaxVoltNumb_numb"
  CMS_GcCMS_MinVoltNumb_numb/1 -> GcCMS_MinVoltNumb_numb/1  "GcCMS_MinVoltNumb_numb"
  CMS_GcCMS_MaxTempNumb_numb/1 -> GcCMS_MaxTempNumb_numb/1  "GcCMS_MaxTempNumb_numb"
  CMS_GcCMS_MinTempNumb_numb/1 -> GcCMS_MinTempNumb_numb/1  "GcCMS_MinTempNumb_numb"
  CMS_GeCMS_DChrgModeDebug_enum/1 -> GeCMS_DChrgModeDebug_enum/1  "GeCMS_DChrgModeDebug_enum"
  CMS_GbCMS_DChrgWkUp_flg/1 -> GbCMS_DChrgWkUp_flg/1  "GbCMS_DChrgWkUp_flg"
  CMS_GeCMS_EvccMode_enum/1 -> GeCMS_EvccMode_enum/1  "GeCMS_EvccMode_enum"
  CMS_GeCMS_AChrgObsr_enum/1 -> GeCMS_AChrgObsr_enum/1  "GeCMS_AChrgObsr_enum"
  CMS_GeCMS_PreThmObsvr_enum/1 -> GeCMS_PreThmObsvr_enum/1  "GeCMS_PreThmObsvr_enum"
  GbWSM_DCWkUpPrs_flg/1 -> CMS_GbCMS_DChrgWkUp_flg/1  "GbWSM_DCWkUpPrs_flg"
  Ground2/1 -> CMS_GeCMS_PreThmObsvr_enum/1
  Ground3/1 -> CMS_GeCMS_EvccMode_enum/1
  Ground4/1 -> CMS_GeCMS_DChrgModeDebug_enum/1
  Constant15/1 -> CMS_GcCMS_MaxVoltNumb_numb/1
  Constant1/1 -> CMS_GcCMS_MinVoltNumb_numb/1
  Constant2/1 -> CMS_GcCMS_MaxTempNumb_numb/1
  Constant3/1 -> CMS_GcCMS_MinTempNumb_numb/1

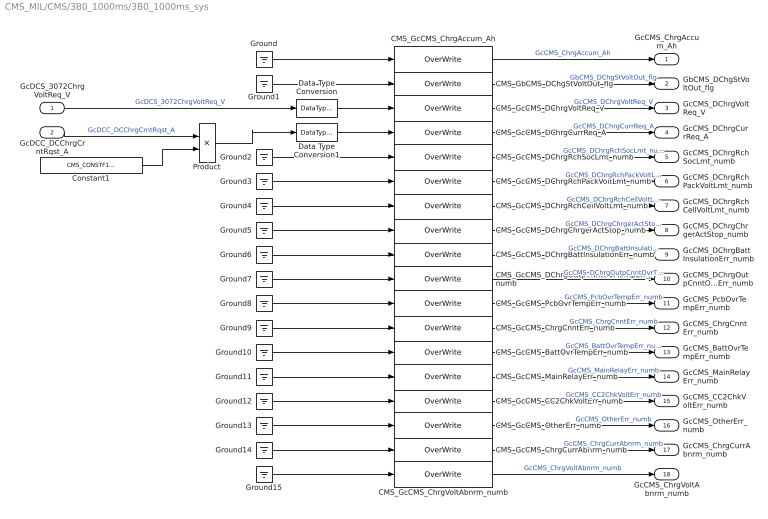
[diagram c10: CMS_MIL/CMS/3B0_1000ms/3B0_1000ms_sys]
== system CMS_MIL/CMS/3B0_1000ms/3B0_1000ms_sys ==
  GcDCS_3072ChrgVoltReq_V : Inport
  GcDCC_DCChrgCrntRqst_A : Inport  Port=2
  CMS_GbCMS_DChgStVoltOut_flg : AIWAYS_Powertrain_BMS_lib/Signals/OverWrite  OverWrite_Value=CbCMS_DChgStVoltOutOvr_flg  OverWrite_flag=CbCMS_DChgStVoltOutOvrSwt_flg
  CMS_GcCMS_BattOvrTempErr_numb : AIWAYS_Powertrain_BMS_lib/Signals/OverWrite  OverWrite_Value=CcCMS_BattOvrTempErrOvr_numb  OverWrite_flag=CbCMS_BattOvrTempErrOvrSwt_flg
  CMS_GcCMS_CC2ChkVoltErr_numb : AIWAYS_Powertrain_BMS_lib/Signals/OverWrite  OverWrite_Value=CcCMS_CC2ChkVoltErrOvr_numb  OverWrite_flag=CbCMS_CC2ChkVoltErrOvrSwt_flg
  CMS_GcCMS_ChrgAccum_Ah : AIWAYS_Powertrain_BMS_lib/Signals/OverWrite  OverWrite_Value=CcCMS_ChrgAccumOvr_Ah  OverWrite_flag=CbCMS_ChrgAccumOvrSwt_flg
  CMS_GcCMS_ChrgCnntErr_numb : AIWAYS_Powertrain_BMS_lib/Signals/OverWrite  OverWrite_Value=CcCMS_ChrgCnntErrOvr_numb  OverWrite_flag=CbCMS_ChrgCnntErrOvrSwt_flg
  CMS_GcCMS_ChrgCurrAbnrm_numb : AIWAYS_Powertrain_BMS_lib/Signals/OverWrite  OverWrite_Value=CcCMS_ChrgCurrAbnrmOvr_numb  OverWrite_flag=CbCMS_ChrgCurrAbnrmOvrSwt_flg
  CMS_GcCMS_ChrgVoltAbnrm_numb : AIWAYS_Powertrain_BMS_lib/Signals/OverWrite  OverWrite_Value=CcCMS_ChrgVoltAbnrmOvr_numb  OverWrite_flag=CbCMS_ChrgVoltAbnrmOvrSwt_flg
  CMS_GcCMS_DChrgBattInsulationErr_numb : AIWAYS_Powertrain_BMS_lib/Signals/OverWrite  OverWrite_Value=CcCMS_DChrgBattInsulationErrOvr_numb  OverWrite_flag=CbCMS_DChrgBattInsulationErrOvrSwt_flg
  CMS_GcCMS_DChrgChrgerActStop_numb : AIWAYS_Powertrain_BMS_lib/Signals/OverWrite  OverWrite_Value=CcCMS_DChrgChrgerActStopOvr_numb  OverWrite_flag=CbCMS_DChrgChrgerActStopOvrSwt_flg
  CMS_GcCMS_DChrgCurrReq_A : AIWAYS_Powertrain_BMS_lib/Signals/OverWrite  OverWrite_Value=CcCMS_DChrgCurrReqOvr_A  OverWrite_flag=CbCMS_DChrgCurrReqOvrSwt_flg
  CMS_GcCMS_DChrgOutpCnntOvrTempErr_numb : AIWAYS_Powertrain_BMS_lib/Signals/OverWrite  OverWrite_Value=CcCMS_DChrgOutpCnntOvrTempErrOvr_numb  OverWrite_flag=CbCMS_DChrgOutpCnntOvrTempErrOvrSwt_flg
  CMS_GcCMS_DChrgRchCellVoltLmt_numb : AIWAYS_Powertrain_BMS_lib/Signals/OverWrite  OverWrite_Value=CcCMS_DChrgRchCellVoltLmtOvr_numb  OverWrite_flag=CbCMS_DChrgRchCellVoltLmtOvrSwt_flg
  CMS_GcCMS_DChrgRchPackVoltLmt_numb : AIWAYS_Powertrain_BMS_lib/Signals/OverWrite  OverWrite_Value=CcCMS_DChrgRchPackVoltLmtOvr_numb  OverWrite_flag=CbCMS_DChrgRchPackVoltLmtOvrSwt_flg
  CMS_GcCMS_DChrgRchSocLmt_numb : AIWAYS_Powertrain_BMS_lib/Signals/OverWrite  OverWrite_Value=CcCMS_DChrgRchSocLmtOvr_numb  OverWrite_flag=CbCMS_DChrgRchSocLmtOvrSwt_flg
  CMS_GcCMS_DChrgVoltReq_V : AIWAYS_Powertrain_BMS_lib/Signals/OverWrite  OverWrite_Value=CcCMS_DChrgVoltReqOvr_V  OverWrite_flag=CbCMS_DChrgVoltReqOvrSwt_flg
  CMS_GcCMS_MainRelayErr_numb : AIWAYS_Powertrain_BMS_lib/Signals/OverWrite  OverWrite_Value=CcCMS_MainRelayErrOvr_numb  OverWrite_flag=CbCMS_MainRelayErrOvrSwt_flg
  CMS_GcCMS_OtherErr_numb : AIWAYS_Powertrain_BMS_lib/Signals/OverWrite  OverWrite_Value=CcCMS_OtherErrOvr_numb  OverWrite_flag=CbCMS_OtherErrOvrSwt_flg
  CMS_GcCMS_PcbOvrTempErr_numb : AIWAYS_Powertrain_BMS_lib/Signals/OverWrite  OverWrite_Value=CcCMS_PcbOvrTempErrOvr_numb  OverWrite_flag=CbCMS_PcbOvrTempErrOvrSwt_flg
  Constant1 : Constant  Value=CMS_CONSTF1_NUMB
  Data Type Conversion : DataTypeConversion
  Data Type Conversion1 : DataTypeConversion
  Ground{,1..15} (16 alike) : Ground
  Product : Product  OutDataTypeStr=Inherit: Inherit via back propagation
  GcCMS_ChrgAccum_Ah : Outport
  GbCMS_DChgStVoltOut_flg : Outport  Port=2
  GcCMS_DChrgVoltReq_V : Outport  Port=3
  GcCMS_DChrgCurrReq_A : Outport  Port=4
  GcCMS_DChrgRchSocLmt_numb : Outport  Port=5
  GcCMS_DChrgRchPackVoltLmt_numb : Outport  Port=6
  GcCMS_DChrgRchCellVoltLmt_numb : Outport  Port=7
  GcCMS_DChrgChrgerActStop_numb : Outport  Port=8
  GcCMS_DChrgBattInsulationErr_numb : Outport  Port=9
  GcCMS_DChrgOutpCnntOvrTempErr_numb : Outport  Port=10
  GcCMS_PcbOvrTempErr_numb : Outport  Port=11
  GcCMS_ChrgCnntErr_numb : Outport  Port=12
  GcCMS_BattOvrTempErr_numb : Outport  Port=13
  GcCMS_MainRelayErr_numb : Outport  Port=14
  GcCMS_CC2ChkVoltErr_numb : Outport  Port=15
  GcCMS_OtherErr_numb : Outport  Port=16
  GcCMS_ChrgCurrAbnrm_numb : Outport  Port=17
  GcCMS_ChrgVoltAbnrm_numb : Outport  Port=18
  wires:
  CMS_GcCMS_ChrgAccum_Ah/1 -> GcCMS_ChrgAccum_Ah/1  "GcCMS_ChrgAccum_Ah"
  CMS_GbCMS_DChgStVoltOut_flg/1 -> GbCMS_DChgStVoltOut_flg/1  "GbCMS_DChgStVoltOut_flg"
  CMS_GcCMS_DChrgVoltReq_V/1 -> GcCMS_DChrgVoltReq_V/1  "GcCMS_DChrgVoltReq_V"
  CMS_GcCMS_DChrgCurrReq_A/1 -> GcCMS_DChrgCurrReq_A/1  "GcCMS_DChrgCurrReq_A"
  CMS_GcCMS_DChrgRchSocLmt_numb/1 -> GcCMS_DChrgRchSocLmt_numb/1  "GcCMS_DChrgRchSocLmt_numb"
  CMS_GcCMS_DChrgRchPackVoltLmt_numb/1 -> GcCMS_DChrgRchPackVoltLmt_numb/1  "GcCMS_DChrgRchPackVoltLmt_numb"
  CMS_GcCMS_DChrgRchCellVoltLmt_numb/1 -> GcCMS_DChrgRchCellVoltLmt_numb/1  "GcCMS_DChrgRchCellVoltLmt_numb"
  GcDCS_3072ChrgVoltReq_V/1 -> Data Type Conversion/1  "GcDCS_3072ChrgVoltReq_V"
  GcDCC_DCChrgCrntRqst_A/1 -> Product/1  "GcDCC_DCChrgCrntRqst_A"
  Ground/1 -> CMS_GcCMS_ChrgAccum_Ah/1
  Ground1/1 -> CMS_GbCMS_DChgStVoltOut_flg/1
  Ground2/1 -> CMS_GcCMS_DChrgRchSocLmt_numb/1
  Ground3/1 -> CMS_GcCMS_DChrgRchPackVoltLmt_numb/1
  Ground4/1 -> CMS_GcCMS_DChrgRchCellVoltLmt_numb/1
  CMS_GcCMS_ChrgVoltAbnrm_numb/1 -> GcCMS_ChrgVoltAbnrm_numb/1  "GcCMS_ChrgVoltAbnrm_numb"
  CMS_GcCMS_ChrgCurrAbnrm_numb/1 -> GcCMS_ChrgCurrAbnrm_numb/1  "GcCMS_ChrgCurrAbnrm_numb"
  CMS_GcCMS_OtherErr_numb/1 -> GcCMS_OtherErr_numb/1  "GcCMS_OtherErr_numb"
  CMS_GcCMS_CC2ChkVoltErr_numb/1 -> GcCMS_CC2ChkVoltErr_numb/1  "GcCMS_CC2ChkVoltErr_numb"
  CMS_GcCMS_MainRelayErr_numb/1 -> GcCMS_MainRelayErr_numb/1  "GcCMS_MainRelayErr_numb"
  CMS_GcCMS_BattOvrTempErr_numb/1 -> GcCMS_BattOvrTempErr_numb/1  "GcCMS_BattOvrTempErr_numb"
  CMS_GcCMS_ChrgCnntErr_numb/1 -> GcCMS_ChrgCnntErr_numb/1  "GcCMS_ChrgCnntErr_numb"
  CMS_GcCMS_PcbOvrTempErr_numb/1 -> GcCMS_PcbOvrTempErr_numb/1  "GcCMS_PcbOvrTempErr_numb"
  CMS_GcCMS_DChrgOutpCnntOvrTempErr_numb/1 -> GcCMS_DChrgOutpCnntOvrTempErr_numb/1  "GcCMS_DChrgOutpCnntOvrTempErr_numb"
  CMS_GcCMS_DChrgBattInsulationErr_numb/1 -> GcCMS_DChrgBattInsulationErr_numb/1  "GcCMS_DChrgBattInsulationErr_numb"
  CMS_GcCMS_DChrgChrgerActStop_numb/1 -> GcCMS_DChrgChrgerActStop_numb/1  "GcCMS_DChrgChrgerActStop_numb"
  Ground5/1 -> CMS_GcCMS_DChrgChrgerActStop_numb/1
  Ground9/1 -> CMS_GcCMS_ChrgCnntErr_numb/1
  Ground8/1 -> CMS_GcCMS_PcbOvrTempErr_numb/1
  Ground7/1 -> CMS_GcCMS_DChrgOutpCnntOvrTempErr_numb/1
  Ground6/1 -> CMS_GcCMS_DChrgBattInsulationErr_numb/1
  Ground10/1 -> CMS_GcCMS_BattOvrTempErr_numb/1
  Ground11/1 -> CMS_GcCMS_MainRelayErr_numb/1
  Ground12/1 -> CMS_GcCMS_CC2ChkVoltErr_numb/1
  Ground13/1 -> CMS_GcCMS_OtherErr_numb/1
  Ground14/1 -> CMS_GcCMS_ChrgCurrAbnrm_numb/1
  Ground15/1 -> CMS_GcCMS_ChrgVoltAbnrm_numb/1
  Data Type Conversion/1 -> CMS_GcCMS_DChrgVoltReq_V/1
  Data Type Conversion1/1 -> CMS_GcCMS_DChrgCurrReq_A/1
  Constant1/1 -> Product/2
  Product/1 -> Data Type Conversion1/1

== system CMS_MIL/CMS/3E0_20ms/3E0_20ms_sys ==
  GaCDP_CellVolt_mV : Inport
  GcUDS_CellVoltNum_numb : Inport  Port=2
  Add1 : Sum  Inputs=+-  OutDataTypeStr=uint16
  Add2 : Sum  Inputs=+-  OutDataTypeStr=uint16
  Add3 : Sum  Inputs=+-  OutDataTypeStr=uint16
  Add4 : Sum  Inputs=+-  OutDataTypeStr=Inherit: Inherit via back propagation
  Add5 : Sum  OutDataTypeStr=Inherit: Inherit via back propagation
  CMS_GcCMS_CellVolt1_V : AIWAYS_Powertrain_BMS_lib/Signals/OverWrite  OverWrite_Value=CcCMS_CellVolt1Ovr_V  OverWrite_flag=CbCMS_CellVolt1OvrSwt_flg
  CMS_GcCMS_CellVolt2_V : AIWAYS_Powertrain_BMS_lib/Signals/OverWrite  OverWrite_Value=CcCMS_CellVolt2Ovr_V  OverWrite_flag=CbCMS_CellVolt2OvrSwt_flg
  CMS_GcCMS_CellVolt3_V : AIWAYS_Powertrain_BMS_lib/Signals/OverWrite  OverWrite_Value=CcCMS_CellVolt3Ovr_V  OverWrite_flag=CbCMS_CellVolt3OvrSwt_flg
  CMS_GcCMS_CellVolt4_V : AIWAYS_Powertrain_BMS_lib/Signals/OverWrite  OverWrite_Value=CcCMS_CellVolt4Ovr_V  OverWrite_flag=CbCMS_CellVolt4OvrSwt_flg
  CMS_GcCMS_CellVoltCnt_numb : AIWAYS_Powertrain_BMS_lib/Signals/OverWrite  OverWrite_Value=CcCMS_CellVoltCntOvr_numb  OverWrite_flag=CbCMS_CellVoltCntOvrSwt_flg
  Constant1 : Constant  Value=CMS_CONST3_NUMB
  Constant13 : Constant  Value=CMS_CONST1_NUMB
  Constant14 : Constant  Value=CMS_CONST0_NUMB
  Constant2 : Constant  Value=CMS_CONST2_NUMB
  Constant21 : Constant  Value=CMS_CONST4_NUMB
  Constant3 : Constant  Value=CMS_CONST1_NUMB
  Constant4 : Constant  Value=CMS_CONST1000_NUMB
  Constant5 : Constant  Value=CMS_CONST1_NUMB
  Data Type Conversion : DataTypeConversion  RndMeth=Round
  Divide6 : Product  Inputs=**  OutDataTypeStr=uint16
  Product1 : Product  Inputs=*/  OutDataTypeStr=single
  Relational Operator1 : RelationalOperator  OutDataTypeStr=boolean
  Selector{,1..3} (4 alike) : Selector  IndexOptions=Index vector (port)  Indices=[1 3]  OutputSizes=1
  Switch1 : Switch  Criteria=u2 ~= 0
  Unit Delay : UnitDelay  SampleTime=-1  StateName=StateName
  GcCMS_CellVoltCnt_numb : Outport
  GcCMS_CellVolt1_V : Outport  Port=2
  GcCMS_CellVolt2_V : Outport  Port=3
  GcCMS_CellVolt3_V : Outport  Port=4
  GcCMS_CellVolt4_V : Outport  Port=5
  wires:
  Constant13/1 -> Add5/2
  Constant14/1 -> Switch1/1
  Add5/1 -> Add4/1, Switch1/3, Divide6/1
  Constant21/1 -> Divide6/2
  Relational Operator1/1 -> Switch1/2
  Unit Delay/1 -> Add5/1
  Switch1/1 -> Unit Delay/1
  Divide6/1 -> Add1/1, Selector3/2, Add3/1, Add2/1, Relational Operator1/1
  GcUDS_CellVoltNum_numb/1 -> Relational Operator1/2  "GcUDS_CellVoltNum_numb"
  Constant1/1 -> Add1/2
  CMS_GcCMS_CellVoltCnt_numb/1 -> GcCMS_CellVoltCnt_numb/1  "GcCMS_CellVoltCnt_numb"
  Add1/1 -> Selector/2
  Constant2/1 -> Add2/2
  Constant3/1 -> Add3/2
  Add2/1 -> Selector1/2
  Add3/1 -> Selector2/2
  Selector3/1 -> CMS_GcCMS_CellVolt4_V/1
  Selector2/1 -> CMS_GcCMS_CellVolt3_V/1
  Selector1/1 -> CMS_GcCMS_CellVolt2_V/1
  Selector/1 -> CMS_GcCMS_CellVolt1_V/1
  CMS_GcCMS_CellVolt1_V/1 -> GcCMS_CellVolt1_V/1  "GcCMS_CellVolt1_V"
  CMS_GcCMS_CellVolt2_V/1 -> GcCMS_CellVolt2_V/1  "GcCMS_CellVolt2_V"
  CMS_GcCMS_CellVolt3_V/1 -> GcCMS_CellVolt3_V/1  "GcCMS_CellVolt3_V"
  CMS_GcCMS_CellVolt4_V/1 -> GcCMS_CellVolt4_V/1  "GcCMS_CellVolt4_V"
  Constant4/1 -> Product1/2
  GaCDP_CellVolt_mV/1 -> Product1/1  "GaCDP_CellVolt_mV"
  Product1/1 -> Data Type Conversion/1
  Data Type Conversion/1 -> Selector3/1, Selector2/1, Selector1/1, Selector/1
  Constant5/1 -> Add4/2
  Add4/1 -> CMS_GcCMS_CellVoltCnt_numb/1

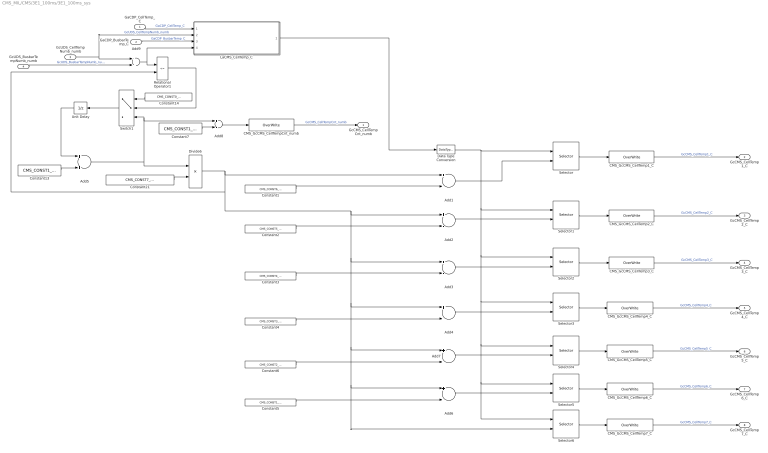
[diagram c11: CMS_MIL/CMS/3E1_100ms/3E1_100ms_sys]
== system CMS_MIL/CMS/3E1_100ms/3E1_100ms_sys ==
  GaCDP_CellTemp_C : Inport
  GaCDP_BusbarTemp_C : Inport  Port=2
  GcUDS_CellTempNumb_numb : Inport  Port=3
  GcUDS_BusbarTempNumb_numb : Inport  Port=4
  Add{1..4,6..7} (6 alike) : Sum  Inputs=+-  OutDataTypeStr=uint16
  Add5 : Sum  OutDataTypeStr=Inherit: Inherit via back propagation
  Add8 : Sum  Inputs=+-  OutDataTypeStr=Inherit: Inherit via back propagation
  Add9 : Sum  OutDataTypeStr=Inherit: Inherit via back propagation
  CMS_GcCMS_CellTemp1_C : AIWAYS_Powertrain_BMS_lib/Signals/OverWrite  OverWrite_Value=CcCMS_CellTemp1Ovr_C  OverWrite_flag=CbCMS_CellTemp1OvrSwt_flg
  CMS_GcCMS_CellTemp2_C : AIWAYS_Powertrain_BMS_lib/Signals/OverWrite  OverWrite_Value=CcCMS_CellTemp2Ovr_C  OverWrite_flag=CbCMS_CellTemp2OvrSwt_flg
  CMS_GcCMS_CellTemp3_C : AIWAYS_Powertrain_BMS_lib/Signals/OverWrite  OverWrite_Value=CcCMS_CellTemp3Ovr_C  OverWrite_flag=CbCMS_CellTemp3OvrSwt_flg
  CMS_GcCMS_CellTemp4_C : AIWAYS_Powertrain_BMS_lib/Signals/OverWrite  OverWrite_Value=CcCMS_CellTemp4Ovr_C  OverWrite_flag=CbCMS_CellTemp4OvrSwt_flg
  CMS_GcCMS_CellTemp5_C : AIWAYS_Powertrain_BMS_lib/Signals/OverWrite  OverWrite_Value=CcCMS_CellTemp5Ovr_C  OverWrite_flag=CbCMS_CellTemp5OvrSwt_flg
  CMS_GcCMS_CellTemp6_C : AIWAYS_Powertrain_BMS_lib/Signals/OverWrite  OverWrite_Value=CcCMS_CellTemp6Ovr_C  OverWrite_flag=CbCMS_CellTemp6OvrSwt_flg
  CMS_GcCMS_CellTemp7_C : AIWAYS_Powertrain_BMS_lib/Signals/OverWrite  OverWrite_Value=CcCMS_CellTemp7Ovr_C  OverWrite_flag=CbCMS_CellTemp7OvrSwt_flg
  CMS_GcCMS_CellTempCnt_numb : AIWAYS_Powertrain_BMS_lib/Signals/OverWrite  OverWrite_Value=CcCMS_CellTempCntOvr_numb  OverWrite_flag=CbCMS_CellTempCntOvrSwt_flg
  Constant1 : Constant  Value=CMS_CONST6_NUMB
  Constant13 : Constant  Value=CMS_CONST1_NUMB
  Constant14 : Constant  Value=CMS_CONST0_NUMB
  Constant2 : Constant  Value=CMS_CONST5_NUMB
  Constant21 : Constant  Value=CMS_CONST7_NUMB
  Constant3 : Constant  Value=CMS_CONST4_NUMB
  Constant4 : Constant  Value=CMS_CONST3_NUMB
  Constant5 : Constant  Value=CMS_CONST1_NUMB
  Constant6 : Constant  Value=CMS_CONST2_NUMB
  Constant7 : Constant  Value=CMS_CONST1_NUMB
  Data Type Conversion : DataTypeConversion  RndMeth=Round
  Divide6 : Product  Inputs=**  OutDataTypeStr=uint16
  LaCMS_CellTemp_C : Subsystem
  Relational Operator1 : RelationalOperator  Operator=<=  OutDataTypeStr=boolean
  Selector{,1..6} (7 alike) : Selector  IndexOptions=Index vector (port)  Indices=[1 3]  OutputSizes=1
  Switch1 : Switch  Criteria=u2 ~= 0
  Unit Delay : UnitDelay  SampleTime=-1  StateName=StateName
  GcCMS_CellTempCnt_numb : Outport
  GcCMS_CellTemp1_C : Outport  Port=2
  GcCMS_CellTemp2_C : Outport  Port=3
  GcCMS_CellTemp3_C : Outport  Port=4
  GcCMS_CellTemp4_C : Outport  Port=5
  GcCMS_CellTemp5_C : Outport  Port=6
  GcCMS_CellTemp6_C : Outport  Port=7
  GcCMS_CellTemp7_C : Outport  Port=8
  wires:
  Add3/1 -> Selector2/2
  Relational Operator1/1 -> Switch1/2
  Add2/1 -> Selector1/2
  Constant13/1 -> Add5/2
  Constant14/1 -> Switch1/1
  Unit Delay/1 -> Add5/1
  Constant21/1 -> Divide6/2
  Constant1/1 -> Add1/2
  Constant2/1 -> Add2/2
  Selector3/1 -> CMS_GcCMS_CellTemp4_C/1
  Add9/1 -> LaCMS_CellTemp_C/4(LcCMS_TempNumb_numb), Relational Operator1/1
  Constant3/1 -> Add3/2
  Switch1/1 -> Unit Delay/1
  Selector2/1 -> CMS_GcCMS_CellTemp3_C/1
  Add5/1 -> Switch1/3, Add8/1, Divide6/1
  Selector1/1 -> CMS_GcCMS_CellTemp2_C/1
  Selector/1 -> CMS_GcCMS_CellTemp1_C/1
  Add1/1 -> Selector/2
  CMS_GcCMS_CellTempCnt_numb/1 -> GcCMS_CellTempCnt_numb/1  "GcCMS_CellTempCnt_numb"
  Add4/1 -> Selector3/2
  Constant4/1 -> Add4/2
  Add6/1 -> Selector5/2
  Constant5/1 -> Add6/2
  Add7/1 -> Selector4/2
  Divide6/1 -> Add1/1, Relational Operator1/2, Add4/1, Add7/1, Selector6/2, Add6/1, Add3/1, Add2/1
  Constant6/1 -> Add7/2
  Selector4/1 -> CMS_GcCMS_CellTemp5_C/1
  Selector5/1 -> CMS_GcCMS_CellTemp6_C/1
  Selector6/1 -> CMS_GcCMS_CellTemp7_C/1
  CMS_GcCMS_CellTemp1_C/1 -> GcCMS_CellTemp1_C/1  "GcCMS_CellTemp1_C"
  CMS_GcCMS_CellTemp2_C/1 -> GcCMS_CellTemp2_C/1  "GcCMS_CellTemp2_C"
  CMS_GcCMS_CellTemp3_C/1 -> GcCMS_CellTemp3_C/1  "GcCMS_CellTemp3_C"
  CMS_GcCMS_CellTemp4_C/1 -> GcCMS_CellTemp4_C/1  "GcCMS_CellTemp4_C"
  CMS_GcCMS_CellTemp5_C/1 -> GcCMS_CellTemp5_C/1  "GcCMS_CellTemp5_C"
  CMS_GcCMS_CellTemp6_C/1 -> GcCMS_CellTemp6_C/1  "GcCMS_CellTemp6_C"
  CMS_GcCMS_CellTemp7_C/1 -> GcCMS_CellTemp7_C/1  "GcCMS_CellTemp7_C"
  Data Type Conversion/1 -> Selector1/1, Selector6/1, Selector5/1, Selector4/1, Selector3/1, Selector2/1, Selector/1
  Add8/1 -> CMS_GcCMS_CellTempCnt_numb/1
  Constant7/1 -> Add8/2
  GaCDP_BusbarTemp_C/1 -> LaCMS_CellTemp_C/3(GaCDP_BusbarTemp_C)  "GaCDP_BusbarTemp_C"
  GaCDP_CellTemp_C/1 -> LaCMS_CellTemp_C/1(GaCDP_CellTemp_C)  "GaCDP_CellTemp_C"
  LaCMS_CellTemp_C/1(LaCMS_CellTemp_C) -> Data Type Conversion/1
  GcUDS_CellTempNumb_numb/1 -> LaCMS_CellTemp_C/2(GcUDS_CellTempNumb_numb), Add9/1  "GcUDS_CellTempNumb_numb"
  GcUDS_BusbarTempNumb_numb/1 -> Add9/2  "GcUDS_BusbarTempNumb_numb"

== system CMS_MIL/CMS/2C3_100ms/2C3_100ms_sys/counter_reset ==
  note: Counter Reset Enabled
  reset : Inport  OutDataTypeStr=boolean
  max_cnt : Inport  Port=2  OutDataTypeStr=uint16
  Constant Value3 : Constant  OutDataTypeStr=uint16
  Constant Value4 : Constant  Value=0  OutDataTypeStr=uint16
  Constant3 : Constant  Value=0  OutDataTypeStr=uint16
  Data Type Conversion2 : DataTypeConversion
  Limiter1 : AIWAYS_Powertrain_BMS_lib/Nonlinear Blocks/Limiter
  Subtraction1 : Sum  RndMeth=Zero
  Switch3 : Switch  Criteria=u2 ~= 0  Threshold=1  RndMeth=Zero
  Unit Delay External IC : AIWAYS_Powertrain_BMS_lib/Delay Blocks/Unit Delay External IC
  cnt_num : Outport
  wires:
  max_cnt/1 -> Data Type Conversion2/1
  Constant3/1 -> Limiter1/2
  Unit Delay External IC/1 -> Subtraction1/2
  Data Type Conversion2/1 -> Limiter1/1, Unit Delay External IC/2
  Limiter1/1 -> Switch3/3
  reset/1 -> Switch3/2
  Switch3/1 -> cnt_num/1, Unit Delay External IC/1
  Constant Value3/1 -> Subtraction1/1
  Constant Value4/1 -> Switch3/1
  Subtraction1/1 -> Limiter1/3

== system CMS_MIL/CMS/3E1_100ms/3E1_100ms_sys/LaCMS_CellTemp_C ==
  GaCDP_CellTemp_C : Inport
  GcUDS_CellTempNumb_numb : Inport  Port=2
  GaCDP_BusbarTemp_C : Inport  Port=3
  LcCMS_TempNumb_numb : Inport  Port=4
  Add8 : Sum  Inputs=+-  OutDataTypeStr=Inherit: Inherit via back propagation
  Array Assignment : Assignment  IndexOptions=Index vector (port)  Indices=1  OutputSizes=1
  CellTempIterator : ForIterator  ResetStates=reset  IterationSource=external  IterationVariableDataType=int8
  Constant1 : Constant  Value=CMS_CONST0_NUMB
  Data Type Conversion : DataTypeConversion  RndMeth=Round
  Mux : Mux  Inputs=7
  Mux1 : Mux  Inputs=7
  Relational Operator2 : RelationalOperator  Operator=<  OutDataTypeStr=boolean
  Selector1 : Selector  IndexOptions=Index vector (port)  Indices=[1 3]  OutputSizes=1
  Selector7 : Selector  IndexOptions=Index vector (port)  Indices=[1 3]  OutputSizes=1
  Switch4 : Switch  Criteria=u2 ~= 0  Threshold=1  RndMeth=Zero
  LaCMS_CellTemp_C : Outport
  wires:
  Mux/1 -> Mux1/1, Mux1/2, Mux1/3, Mux1/7, Mux1/6, Mux1/5, Mux1/4
  Mux1/1 -> Array Assignment/1
  Constant1/1 -> Data Type Conversion/1
  LcCMS_TempNumb_numb/1 -> CellTempIterator/1
  Switch4/1 -> Array Assignment/2
  Array Assignment/1 -> LaCMS_CellTemp_C/1
  GaCDP_CellTemp_C/1 -> Selector7/1
  CellTempIterator/1 -> Array Assignment/3, Selector7/2, Relational Operator2/2, Add8/1
  Relational Operator2/1 -> Switch4/2
  GcUDS_CellTempNumb_numb/1 -> Add8/2, Relational Operator2/1
  Selector7/1 -> Switch4/3
  Selector1/1 -> Switch4/1
  GaCDP_BusbarTemp_C/1 -> Selector1/1
  Add8/1 -> Selector1/2
  Data Type Conversion/1 -> Mux/6, Mux/7, Mux/5, Mux/4, Mux/3, Mux/2, Mux/1

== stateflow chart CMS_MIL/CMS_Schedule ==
  (default) -> (junction 50)
  (junction 50) -> (junction 13) : { CMS_09D_10ms; }
  (junction 13) -> (junction 150) : { TimeCounter20ms ++; TimeCounter100ms ++; TimeCounter500ms ++; TimeCounter1000ms ++; }
  (junction 150) -> (junction 422) : [TimeCounter20ms >= Const20ms]
  (junction 150) -> (junction 424)
  (junction 422) -> (junction 424) : { CMS_3E0_20ms; TimeCounter20ms = 0; }
  (junction 424) -> (junction 503) : [TimeCounter100ms >= Const100ms]
  (junction 424) -> (junction 505)
  (junction 503) -> (junction 505) : {CMS_2C0_100ms; CMS_2C2_100ms; CMS_2C3_100ms; CMS_2C7_100ms; CMS_2C8_100ms; CMS_2CA_100ms; CMS_2CD_100ms; CMS_2CE_100ms; CMS_2CF_100ms; CMS_3E1_100ms; TimeCounter100ms = 0; }
  (junction 505) -> (junction 509) : [TimeCounter500ms >= Const500ms]
  (junction 505) -> (junction 512)
  (junction 509) -> (junction 512) : {CMS_318_500ms; TimeCounter500ms = 0; }
  (junction 512) -> (junction 533) : [TimeCounter1000ms >= Const1000ms]
  (junction 512) -> (junction 536)
  (junction 533) -> (junction 536) : {CMS_3B0_1000ms; TimeCounter1000ms = 0; }
  data: TimeCounter20ms local uint8; Const100ms constant uint8 =10; TimeCounter100ms local uint8; Const20ms constant uint8 =2; Const500ms constant uint8 =50; TimeCounter500ms local uint8; TimeCounter1000ms local uint8; Const1000ms constant uint8 =100
  events: output FUNCTION_CALL_EVENT; output FUNCTION_CALL_EVENT; output FUNCTION_CALL_EVENT; output FUNCTION_CALL_EVENT; output FUNCTION_CALL_EVENT; output FUNCTION_CALL_EVENT; output FUNCTION_CALL_EVENT; output FUNCTION_CALL_EVENT; output FUNCTION_CALL_EVENT; output FUNCTION_CALL_EVENT; output FUNCTION_CALL_EVENT; output FUNCTION_CALL_EVENT; output FUNCTION_CALL_EVENT; output FUNCTION_CALL_EVENT
